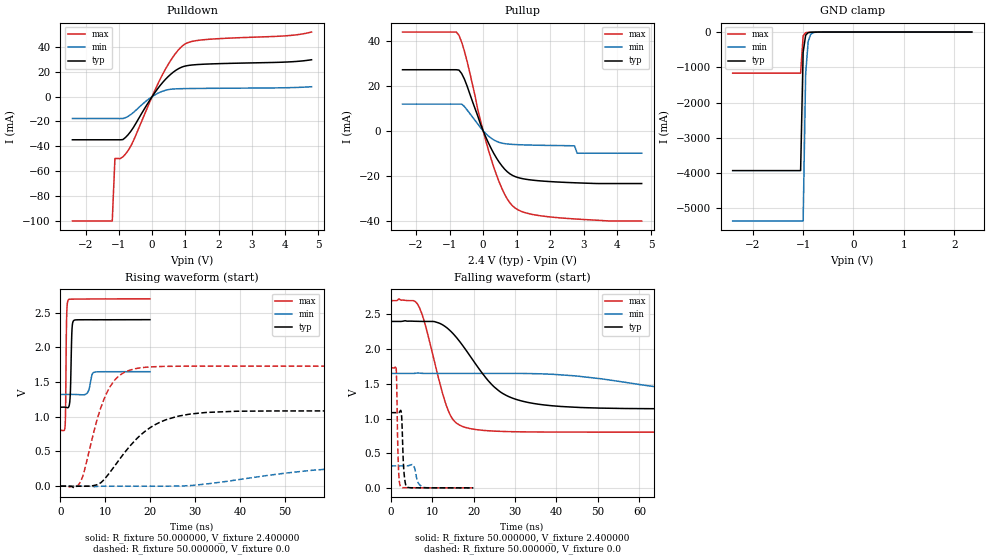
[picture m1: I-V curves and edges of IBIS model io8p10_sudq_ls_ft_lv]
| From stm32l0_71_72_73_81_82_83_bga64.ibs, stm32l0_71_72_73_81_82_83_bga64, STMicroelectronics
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|   Model io8p10_sudq_ls_ft_lv
[Model]  io8p10_sudq_ls_ft_lv
Model_type I/O
Polarity   Non-Inverting
Enable   Active-Low
Vinl =   0.720000V
Vinh =   1.680000V
Vmeas =  1.200000V
Cref =   50.000000pF
Rref =   100.000000M
Vref =   0.0V
C_comp   2.317700pF   2.286600pF   2.332700pF
[Temperature Range]   25.000000   0.105000k   -40.000000
[Pullup Reference]   2.400000V   1.650000V   2.700000V
[Pulldown Reference]   0.0V   0.0V   0.0V
[POWER Clamp Reference]   2.400000V   1.650000V   2.700000V
[GND Clamp Reference]   0.0V   0.0V   0.0V
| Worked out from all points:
|   slope of the pulldown table from 0 to 0.36 V, typ, clamps not added: 28.4 ohm
|   slope of the pullup table from 0 to 0.36 V, typ, clamps not added: 32.2 ohm
|   GND clamp passes 1 mA (typ) near -0.65 V on its own axis
|   rising waveform, R_fixture 50.000000, V_fixture 2.400000: 20-80 % time 276ps typ, 632ps min, 184ps max; typ from 1.14 V to 2.4 V
|   rising waveform, R_fixture 50.000000, V_fixture 0.0: 20-80 % time 9.37ns typ, 24.8ns min, 4.83ns max; typ from 0 V to 1.08 V
|   falling waveform, R_fixture 50.000000, V_fixture 2.400000: 20-80 % time 10.1ns typ, 27.4ns min, 4.97ns max; typ from 2.4 V to 1.14 V
|   falling waveform, R_fixture 50.000000, V_fixture 0.0: 20-80 % time 456ps typ, 833ps min, 355ps max; typ from 1.08 V to 0 V
[Pulldown]
|Voltage   I(typ)   I(min)   I(max)
-2.4V     -34.7mA    -17.61mA   -100mA
-1.2V     -34.7mA    -17.61mA   -100mA
-1.12V    -34.7mA    -17.61mA   -49.77mA
-960mV    -34.7mA    -17.61mA   -49.77mA
-720mV    -30.52mA   -15.81mA   -43.24mA
-560mV    -24.66mA   -12.69mA   -35.31mA
-80mV     -3.3mA     -1.497mA   -4.982mA
320mV     11.47mA    4.39mA     18.08mA
640mV     19.72mA    6.139mA    32.34mA
960mV     24.32mA    6.432mA    41.77mA
1.52V     26.01mA    6.613mA    45.64mA
4.8V      29.64mA    7.944mA    51.92mA
[Pullup]
|Voltage   I(typ)   I(min)   I(max)
-2.4V     27.21mA    11.89mA    44.01mA
-800mV    27.21mA    11.89mA    44.01mA
-720mV    27.06mA    11.89mA    42.53mA
-560mV    23.11mA    10.86mA    35.65mA
-80mV     3.011mA    1.496mA    4.671mA
320mV     -10.16mA   -4.078mA   -16.34mA
640mV     -17.08mA   -5.718mA   -28.28mA
960mV     -20.45mA   -6.129mA   -34.49mA
2V        -22.64mA   -6.529mA   -38.4mA
2.72V     -23.16mA   -6.7mA     -39.27mA
2.8V      -23.2mA    -10mA      -39.35mA
4.72V     -23.5mA    -10mA      -40.2mA
[GND_clamp]
|Voltage   I(typ)   I(min)   I(max)
-2.4V     -3.929A    -5.359A    -1.166A
-1.05V    -3.929A    -5.359A    -1.166A
-1V       -574.5mA   -5.359A    -109.1mA
-950mV    -90.02mA   -1.192A    -18.55mA
-900mV    -18.41mA   -269.7mA   -9.049mA
-850mV    -6.764mA   -63.59mA   -6.579mA
-800mV    -4.027mA   -16.66mA   -4.859mA
-650mV    -1.043mA   -1.218mA   -1.146mA
2.35V     0A         0A         0A
[POWER_clamp]
|Voltage   I(typ)   I(min)   I(max)
-2.4V     0A         0A         0A
0V        0A         0A         0A
[Ramp]
| variable   typ   min   max
dV/dt_r  0.65070/9.36030n   0.18997/24.76198n   1.03800/4.81922n
dV/dt_f  0.75696/10.10042n   0.19686/27.37086n   1.13786/4.96486n
R_load = 50.000000
[Rising Waveform]
R_fixture= 50.000000
V_fixture= 2.400000
V_fixture_min= 1.650000
V_fixture_max= 2.700000
|time   V(typ)   V(min)   V(max)
0s        1.138V     1.322V     803.6mV
1.041ns   1.138V     1.322V     870.2mV
1.161ns   1.137V     1.322V     1.19V
1.361ns   1.134V     1.322V     2.386V
1.722ns   1.133V     1.322V     2.683V
2.122ns   1.249V     1.322V     2.695V
2.563ns   2.246V     1.322V     2.696V
2.963ns   2.387V     1.322V     2.696V
7.608ns   2.399V     1.643V     2.699V
19.94ns   2.4V       1.65V      2.7V
[Rising Waveform]
R_fixture= 50.000000
V_fixture= 0.0
V_fixture_min= 0.0
V_fixture_max= 0.0
|time   V(typ)   V(min)   V(max)
0s        -472.8nV   -2.959uV   -194nV
4.505ns   -904.9uV   98.1uV     64.93mV
8.509ns   31.32mV    -905.1uV   1.033V
11.51ns   241mV      -198.6uV   1.478V
14.01ns   460mV      -201.1uV   1.632V
18.02ns   745.6mV    -191.8uV   1.708V
26.03ns   1.006V     1.047mV    1.729V
39.04ns   1.079V     87.63mV    1.73V
80.58ns   1.085V     302.6mV    1.73V
249.2ns   1.085V     316.6mV    1.73V
[Falling Waveform]
R_fixture= 50.000000
V_fixture= 2.400000
V_fixture_min= 1.650000
V_fixture_max= 2.700000
|time   V(typ)   V(min)   V(max)
0s        2.4V       1.65V      2.7V
6.507ns   2.401V     1.657V     2.65V
8.008ns   2.4V       1.651V     2.424V
14.01ns   2.286V     1.65V      1.098V
16.02ns   2.159V     1.65V      927.6mV
20.52ns   1.784V     1.65V      840.8mV
29.03ns   1.302V     1.65V      810.3mV
45.55ns   1.159V     1.608V     803.9mV
96.1ns    1.138V     1.344V     803.6mV
249.2ns   1.138V     1.322V     803.6mV
[Falling Waveform]
R_fixture= 50.000000
V_fixture= 0.0
V_fixture_min= 0.0
V_fixture_max= 0.0
|time   V(typ)   V(min)   V(max)
0s        1.085V     316.6mV    1.73V
1.321ns   1.085V     316.6mV    1.745V
1.441ns   1.085V     316.6mV    1.586V
1.882ns   1.084V     316.6mV    320mV
2.442ns   1.118V     316.6mV    17.18mV
2.683ns   1.014V     316.6mV    5.904mV
3.203ns   248.1mV    316.4mV    1.705mV
3.924ns   14.55mV    316.4mV    1.473mV
7.928ns   374uV      7.833mV    915.7uV
19.94ns   -472.8nV   -2.959uV   -194nV
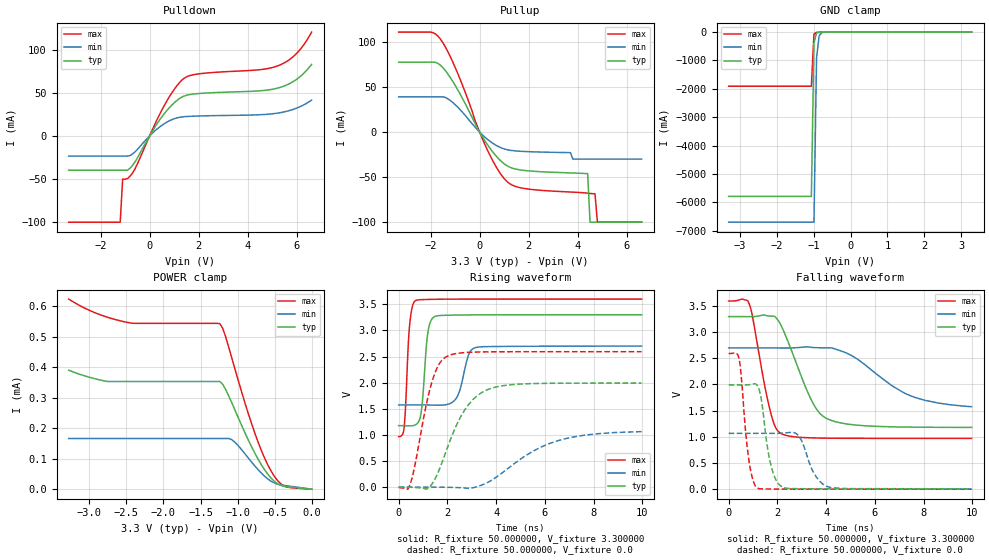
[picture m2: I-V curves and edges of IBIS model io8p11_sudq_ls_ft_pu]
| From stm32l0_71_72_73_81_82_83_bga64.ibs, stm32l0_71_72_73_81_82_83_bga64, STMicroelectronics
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|   Model io8p11_sudq_ls_ft_pu
[Model]  io8p11_sudq_ls_ft_pu
Model_type I/O
Polarity   Non-Inverting
Enable   Active-Low
Vinl =   0.990000V
Vinh =   2.310000V
Vmeas =  1.650000V
Cref =   50.000000pF
Rref =   100.000000M
Vref =   0.0V
C_comp   2.343000pF   2.309800pF   2.393900pF
[Temperature Range]   25.000000   0.125000k   -40.000000
[Pullup Reference]   3.300000V   2.700000V   3.600000V
[Pulldown Reference]   0.0V   0.0V   0.0V
[POWER Clamp Reference]   3.300000V   2.700000V   3.600000V
[GND Clamp Reference]   0.0V   0.0V   0.0V
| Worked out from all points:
|   slope of the pulldown table from 0 to 0.495 V, typ, clamps not added: 22.6 ohm
|   slope of the pullup table from 0 to 0.495 V, typ, clamps not added: 23.9 ohm
|   GND clamp passes 1 mA (typ) near -0.64 V on its own axis
|   rising waveform, R_fixture 50.000000, V_fixture 3.300000: 20-80 % time 209ps typ, 361ps min, 167ps max; typ from 1.18 V to 3.3 V
|   rising waveform, R_fixture 50.000000, V_fixture 0.0: 20-80 % time 1.17ns typ, 2.21ns min, 698ps max; typ from 0.001 V to 1.99 V
|   falling waveform, R_fixture 50.000000, V_fixture 3.300000: 20-80 % time 1.12ns typ, 2.07ns min, 641ps max; typ from 3.3 V to 1.18 V
|   falling waveform, R_fixture 50.000000, V_fixture 0.0: 20-80 % time 388ps typ, 564ps min, 310ps max; typ from 1.99 V to 0.001 V
[Pulldown]
|Voltage   I(typ)   I(min)   I(max)
-3.3V     -39.8mA    -23.38mA   -100mA
-1.2V     -39.8mA    -23.38mA   -100mA
-1.1V     -39.8mA    -23.38mA   -50.11mA
-900mV    -39.8mA    -23.38mA   -49.43mA
-700mV    -34.25mA   -21mA      -43.13mA
600mV     25.84mA    14.18mA    35.34mA
1V        38.32mA    19.82mA    53.81mA
1.4V      46.09mA    22.19mA    66.63mA
2V        49.05mA    23.02mA    71.83mA
5.2V      55.23mA    26.32mA    80.92mA
6V        65.77mA    32.26mA    95.84mA
6.6V      82.81mA    41.44mA    120.2mA
[Pullup]
|Voltage   I(typ)   I(min)   I(max)
-3.3V     77.64mA    39.15mA    111mA
-2V       77.64mA    39.15mA    111mA
-1.6V     74.25mA    39.15mA    103.3mA
-900mV    47.24mA    27.86mA    65.53mA
300mV     -13.29mA   -7.65mA    -18.99mA
1.2V      -38.62mA   -20mA      -56.79mA
3.7V      -45.29mA   -22.8mA    -66.51mA
4.4V      -46.01mA   -30mA      -67.77mA
4.5V      -100mA     -30mA      -68.06mA
4.7V      -100mA     -30mA      -68.41mA
4.8V      -100mA     -30mA      -100mA
6.6V      -100mA     -30mA      -100mA
[GND_clamp]
|Voltage   I(typ)   I(min)   I(max)
-3.3V     -5.787A    -6.696A    -1.906A
-1.06V    -5.787A    -6.696A    -1.906A
-990mV    -393.4mA   -6.696A    -70.75mA
-920mV    -33.02mA   -919.4mA   -10.9mA
-850mV    -6.829mA   -131.3mA   -6.521mA
-780mV    -3.478mA   -21.06mA   -4.208mA
3.28V     0A         0A         0A
[POWER_clamp]
|Voltage   I(typ)   I(min)   I(max)
-3.28V    390.5uA    166.4uA    624.1uA
-2.76V    353.6uA    166.4uA    564.6uA
-2.44V    353.6uA    166.4uA    545.3uA
-1.24V    353.6uA    166.4uA    543.5uA
-1.2V     344.2uA    166.4uA    528.2uA
-1.16V    327.1uA    166.4uA    499.5uA
-1.04V    262.6uA    155.2uA    398.8uA
-760mV    115.1uA    74.4uA     179.3uA
-560mV    39.86uA    27.94uA    65.07uA
-440mV    15uA       15.53uA    23.15uA
-360mV    8.745uA    12.05uA    9.089uA
0V        0A         0A         0A
[Ramp]
| variable   typ   min   max
dV/dt_r  1.19462/1.17303n   0.61247/2.09049n   1.55541/0.69549n
dV/dt_f  1.27146/1.11827n   0.59124/1.83665n   1.57744/0.63930n
R_load = 50.000000
[Rising Waveform]
R_fixture= 50.000000
V_fixture= 3.300000
V_fixture_min= 2.700000
V_fixture_max= 3.600000
|time   V(typ)   V(min)   V(max)
0s        1.178V     1.575V     967.9mV
220.2ps   1.177V     1.575V     1.13V
440.4ps   1.174V     1.575V     3.055V
700.7ps   1.198V     1.575V     3.572V
940.9ps   1.496V     1.575V     3.589V
1.221ns   3.023V     1.573V     3.593V
1.481ns   3.267V     1.571V     3.595V
2.362ns   3.294V     1.701V     3.599V
3.123ns   3.298V     2.666V     3.6V
9.97ns    3.3V       2.7V       3.6V
[Rising Waveform]
R_fixture= 50.000000
V_fixture= 0.0
V_fixture_min= 0.0
V_fixture_max= 0.0
|time   V(typ)   V(min)   V(max)
0s        1.228mV    1.825mV    -5.004mV
460.5ps   320.4uV    1.809mV    45.06mV
1.341ns   45.31mV    1.995mV    1.977V
1.642ns   310.2mV    1.629mV    2.342V
1.962ns   707.7mV    -435.1uV   2.499V
2.422ns   1.237V     -6.561mV   2.562V
2.843ns   1.567V     -20.6mV    2.58V
3.744ns   1.883V     114.2mV    2.59V
6.326ns   1.989V     859.2mV    2.593V
9.97ns    1.993V     1.064V     2.593V
[Falling Waveform]
R_fixture= 50.000000
V_fixture= 3.300000
V_fixture_min= 2.700000
V_fixture_max= 3.600000
|time   V(typ)   V(min)   V(max)
0s        3.3V       2.7V       3.6V
840.8ps   3.299V     2.7V       3.545V
1.682ns   3.311V     2.7V       1.54V
1.902ns   3.298V     2.7V       1.2V
2.142ns   3.139V     2.7V       1.064V
3.343ns   1.751V     2.715V     978.4mV
3.984ns   1.358V     2.702V     972.2mV
5.045ns   1.232V     2.554V     969.1mV
7.628ns   1.183V     1.754V     968mV
9.97ns    1.178V     1.575V     967.9mV
[Falling Waveform]
R_fixture= 50.000000
V_fixture= 0.0
V_fixture_min= 0.0
V_fixture_max= 0.0
|time   V(typ)   V(min)   V(max)
0s        1.993V     1.064V     2.593V
420.4ps   1.992V     1.064V     2.506V
820.8ps   1.995V     1.064V     580.8mV
1.181ns   1.974V     1.064V     16.75mV
1.742ns   442.5mV    1.064V     -2.385mV
2.222ns   33.24mV    1.068V     -3.285mV
2.883ns   4.461mV    1.01V      -4.104mV
3.504ns   3.224mV    297.6mV    -4.555mV
4.004ns   2.633mV    51.89mV    -4.752mV
9.97ns    1.228mV    1.825mV    -5.004mV
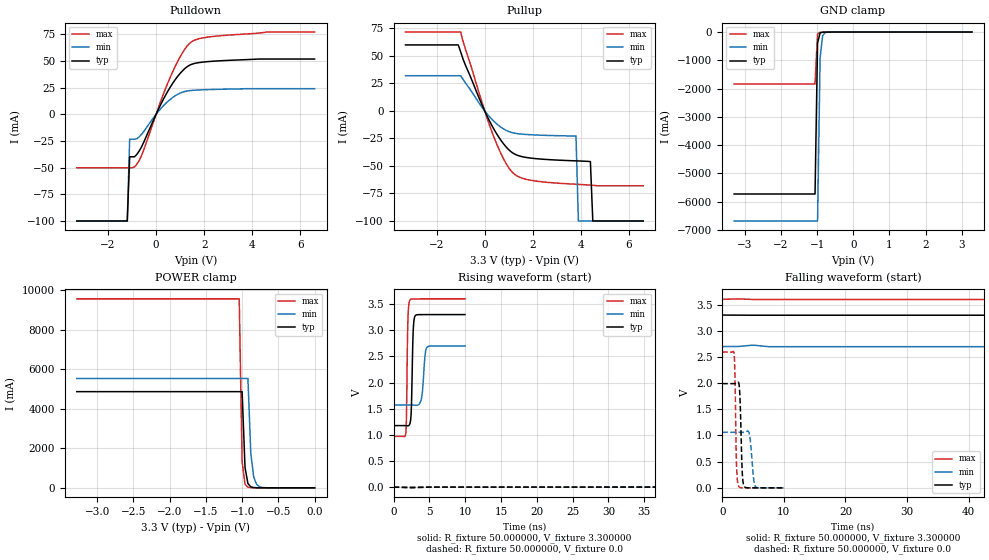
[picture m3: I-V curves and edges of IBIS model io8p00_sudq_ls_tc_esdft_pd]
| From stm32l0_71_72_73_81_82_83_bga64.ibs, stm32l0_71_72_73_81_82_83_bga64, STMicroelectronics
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|   Model io8p00_sudq_ls_tc_esdft_pd
[Model]  io8p00_sudq_ls_tc_esdft_pd
Model_type I/O
Polarity   Non-Inverting
Enable   Active-Low
Vinl =   0.990000V
Vinh =   2.310000V
Vmeas =  1.650000V
Cref =   50.000000pF
Rref =   100.000000M
Vref =   0.0V
C_comp   2.248300pF   2.207300pF   2.311900pF
[Temperature Range]   25.000000   0.125000k   -40.000000
[Pullup Reference]   3.300000V   2.700000V   3.600000V
[Pulldown Reference]   0.0V   0.0V   0.0V
[POWER Clamp Reference]   3.300000V   2.700000V   3.600000V
[GND Clamp Reference]   0.0V   0.0V   0.0V
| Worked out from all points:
|   slope of the pulldown table from 0 to 0.495 V, typ, clamps not added: 22.6 ohm
|   slope of the pullup table from 0 to 0.495 V, typ, clamps not added: 23.9 ohm
|   GND clamp passes 1 mA (typ) near -0.64 V on its own axis
|   POWER clamp passes 1 mA (typ) near -0.63 V on its own axis
|   rising waveform, R_fixture 50.000000, V_fixture 3.300000: 20-80 % time 209ps typ, 363ps min, 164ps max; typ from 1.18 V to 3.3 V
|   rising waveform, R_fixture 50.000000, V_fixture 0.0: 20-80 % time 210ns typ, 427ns min, 103ns max; typ from 0 V to 1.99 V
|   falling waveform, R_fixture 50.000000, V_fixture 3.300000: 20-80 % time 193ns typ, 384ns min, 106ns max; typ from 3.3 V to 1.18 V
|   falling waveform, R_fixture 50.000000, V_fixture 0.0: 20-80 % time 290ps typ, 458ps min, 227ps max; typ from 1.99 V to 0 V
[Pulldown]
|Voltage   I(typ)   I(min)   I(max)
-3.3V     -100mA     -100mA     -50.11mA
-1.2V     -100mA     -100mA     -50.11mA
-1.1V     -39.8mA    -23.38mA   -50.11mA
-900mV    -39.8mA    -23.38mA   -49.43mA
-600mV    -30.26mA   -18.59mA   -38.38mA
500mV     22.11mA    12.28mA    30.06mA
900mV     35.58mA    18.71mA    49.62mA
1.3V      44.74mA    21.88mA    64.23mA
1.7V      48.13mA    22.72mA    70.3mA
2.4V      49.79mA    23.3mA     73.03mA
4.6V      51.8mA     24mA       77.1mA
6.6V      51.8mA     24mA       77.1mA
[Pullup]
|Voltage   I(typ)   I(min)   I(max)
-3.3V     60mA       32mA       71.7mA
-1.1V     60mA       32mA       71.7mA
-1V       53.5mA     32mA       71.7mA
-100mV    4.893mA    2.926mA    6.861mA
400mV     -17.21mA   -9.812mA   -24.69mA
900mV     -32.92mA   -17.72mA   -48.15mA
1.3V      -39.75mA   -20.4mA    -58.47mA
3.8V      -45.36mA   -22.8mA    -66.6mA
3.9V      -45.44mA   -100mA     -66.72mA
4.4V      -46mA      -100mA     -67.4mA
4.5V      -100mA     -100mA     -67.56mA
6.6V      -100mA     -100mA     -68mA
[GND_clamp]
|Voltage   I(typ)   I(min)   I(max)
-3.3V     -5.732A    -6.689A    -1.842A
-1.06V    -5.732A    -6.689A    -1.842A
-990mV    -389.4mA   -6.689A    -68.35mA
-920mV    -32.58mA   -918.2mA   -10.73mA
-850mV    -6.776mA   -131mA     -6.518mA
-780mV    -3.484mA   -21.02mA   -4.216mA
3.28V     74.9uA     89.13uA    52.44uA
[POWER_clamp]
|Voltage   I(typ)   I(min)   I(max)
-3.28V    4.87A      5.538A     9.569A
-1.04V    4.87A      5.538A     9.569A
-1V       4.87A      5.538A     1.315A
-960mV    1.032A     5.538A     186.5mA
-920mV    222.2mA    5.538A     31.64mA
-880mV    50.73mA    1.734A     9.582mA
-840mV    13.93mA    544.8mA    5.668mA
-800mV    5.556mA    172.7mA    4.276mA
-760mV    3.231mA    55.84mA    3.297mA
-680mV    1.597mA    6.983mA    1.741mA
0V        0A         0A         0A
[Ramp]
| variable   typ   min   max
dV/dt_r  1.19412/0.20970u   0.60618/0.42769u   1.55520/0.10339u
dV/dt_f  1.27242/0.19304u   0.63624/0.38498u   1.57760/0.10596u
R_load = 50.000000
[Rising Waveform]
R_fixture= 50.000000
V_fixture= 3.300000
V_fixture_min= 2.700000
V_fixture_max= 3.600000
|time   V(typ)   V(min)   V(max)
0s        1.176V     1.571V     969.9mV
1.702ns   1.176V     1.571V     1.02V
2.002ns   1.172V     1.571V     3.192V
2.262ns   1.207V     1.571V     3.571V
2.482ns   1.517V     1.571V     3.595V
2.743ns   2.989V     1.569V     3.598V
2.963ns   3.261V     1.567V     3.599V
3.904ns   3.298V     1.705V     3.599V
4.645ns   3.299V     2.67V      3.599V
9.97ns    3.299V     2.698V     3.599V
[Rising Waveform]
R_fixture= 50.000000
V_fixture= 0.0
V_fixture_min= 0.0
V_fixture_max= 0.0
|time   V(typ)   V(min)   V(max)
0s        1.794nV    13.74nV    3.926nV
55.06ns   275.8uV    -16.63uV   81.26mV
112.6ns   80.83mV    125.2uV    963.1mV
177.7ns   429mV      2.008mV    1.946V
215.2ns   684.1mV    10.02mV    2.277V
272.8ns   1.075V     45.95mV    2.493V
412.9ns   1.683V     221.8mV    2.581V
545.5ns   1.894V     454.1mV    2.591V
858.4ns   1.983V     872.6mV    2.592V
1.246us   1.99V      1.06V      2.592V
[Falling Waveform]
R_fixture= 50.000000
V_fixture= 3.300000
V_fixture_min= 2.700000
V_fixture_max= 3.600000
|time   V(typ)   V(min)   V(max)
0s        3.299V     2.698V     3.599V
82.58ns   3.296V     2.695V     3.494V
145.1ns   3.209V     2.695V     2.587V
210.2ns   2.863V     2.692V     1.628V
247.7ns   2.608V     2.682V     1.251V
282.8ns   2.359V     2.664V     1.094V
397.9ns   1.617V     2.541V     997.6mV
510.5ns   1.321V     2.352V     978.9mV
863.4ns   1.191V     1.753V     970.4mV
1.246us   1.176V     1.571V     969.9mV
[Falling Waveform]
R_fixture= 50.000000
V_fixture= 0.0
V_fixture_min= 0.0
V_fixture_max= 0.0
|time   V(typ)   V(min)   V(max)
0s        1.99V      1.06V      2.592V
1.922ns   1.99V      1.06V      2.568V
2.322ns   1.991V     1.06V      448.6mV
2.643ns   2.015V     1.06V      36.53mV
2.883ns   1.723V     1.06V      6.041mV
3.263ns   276.2mV    1.06V      445.6uV
3.524ns   40.19mV    1.06V      159.9uV
4.404ns   152uV      1.027V     69.55uV
5.385ns   47.55uV    28.29mV    33.7uV
9.97ns    1.794nV    13.74nV    3.926nV
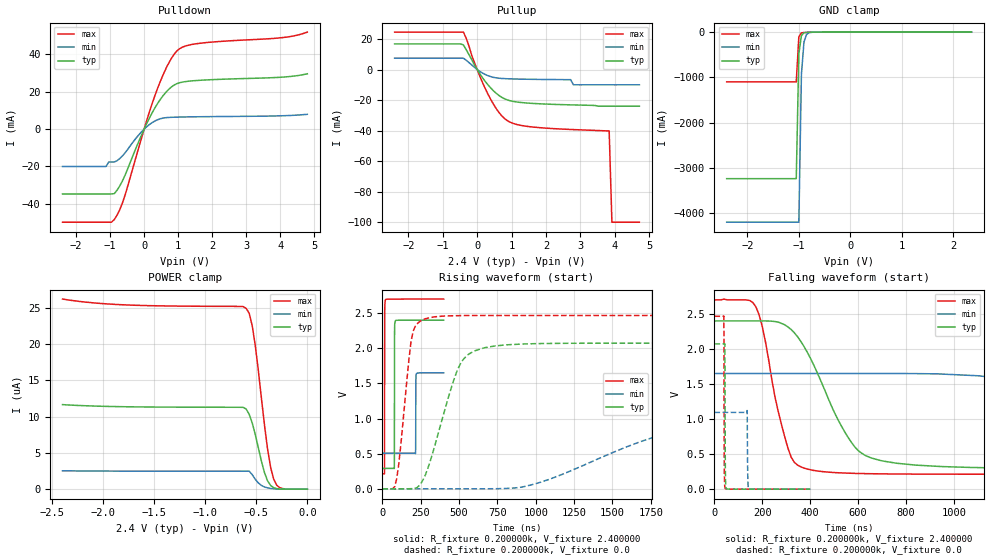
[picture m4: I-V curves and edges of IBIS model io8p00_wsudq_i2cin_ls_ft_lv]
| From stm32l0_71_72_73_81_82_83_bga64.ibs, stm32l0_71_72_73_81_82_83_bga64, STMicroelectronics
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|   Model io8p00_wsudq_i2cin_ls_ft_lv
[Model]  io8p00_wsudq_i2cin_ls_ft_lv
Model_type I/O
Polarity   Non-Inverting
Enable   Active-Low
Vinl =   0.720000V
Vinh =   1.680000V
Vmeas =  1.200000V
Cref =   50.000000pF
Rref =   100.000000M
Vref =   0.0V
C_comp   2.943600pF   2.919700pF   2.965100pF
[Temperature Range]   25.000000   0.105000k   -40.000000
[Pullup Reference]   2.400000V   1.650000V   2.700000V
[Pulldown Reference]   0.0V   0.0V   0.0V
[POWER Clamp Reference]   2.400000V   1.650000V   2.700000V
[GND Clamp Reference]   0.0V   0.0V   0.0V
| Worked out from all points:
|   slope of the pulldown table from 0 to 0.36 V, typ, clamps not added: 28.5 ohm
|   slope of the pullup table from 0 to 0.36 V, typ, clamps not added: 32.2 ohm
|   GND clamp passes 1 mA (typ) near -0.65 V on its own axis
|   rising waveform, R_fixture 0.200000k, V_fixture 2.400000: 20-80 % time 682ps typ, 843ps min, 768ps max; typ from 0.291 V to 2.4 V
|   rising waveform, R_fixture 0.200000k, V_fixture 0.0: 20-80 % time 169ns typ, 819ns min, 66.3ns max; typ from 0 V to 2.07 V
|   falling waveform, R_fixture 0.200000k, V_fixture 2.400000: 20-80 % time 180ns typ, 726ns min, 89.5ns max; typ from 2.4 V to 0.291 V
|   falling waveform, R_fixture 0.200000k, V_fixture 0.0: 20-80 % time 1.22ns typ, 1.77ns min, 1.04ns max; typ from 2.07 V to 0 V
[Pulldown]
|Voltage   I(typ)   I(min)   I(max)
-2.4V     -34.71mA   -20mA      -49.82mA
-1.12V    -34.71mA   -20mA      -49.82mA
-1.04V    -34.71mA   -17.6mA    -49.82mA
-880mV    -34.55mA   -17.6mA    -48.46mA
-560mV    -24.65mA   -12.68mA   -35.33mA
0V        326fA      0A         140fA
400mV     13.84mA    5.066mA    22.03mA
720mV     21.24mA    6.254mA    35.26mA
1.04V     24.82mA    6.464mA    43.03mA
1.6V      26.11mA    6.627mA    45.88mA
4V        27.76mA    7.125mA    48.87mA
4.8V      29.64mA    7.94mA     51.96mA
[Pullup]
|Voltage   I(typ)   I(min)   I(max)
-2.4V     16.77mA    7.419mA    24.51mA
-400mV    16.1mA     7.419mA    24.51mA
0V        80fA       6.14pA     10fA
320mV     -10.16mA   -4.078mA   -16.34mA
640mV     -17.08mA   -5.718mA   -28.28mA
960mV     -20.45mA   -6.128mA   -34.49mA
1.76V     -22.39mA   -6.47mA    -37.97mA
2.72V     -23.16mA   -6.64mA    -39.27mA
2.8V      -23.2mA    -10mA      -39.35mA
3.84V     -24mA      -10mA      -40.2mA
3.92V     -24mA      -10mA      -100mA
4.72V     -24mA      -10mA      -100mA
[GND_clamp]
|Voltage   I(typ)   I(min)   I(max)
-2.4V     -3.237A    -4.198A    -1.1A
-1.05V    -3.237A    -4.198A    -1.1A
-1V       -475.8mA   -4.198A    -104.2mA
-950mV    -76.24mA   -935.4mA   -18.39mA
-900mV    -16.61mA   -212.9mA   -9.105mA
-850mV    -6.547mA   -50.94mA   -6.589mA
-800mV    -3.998mA   -13.81mA   -4.86mA
-650mV    -1.043mA   -1.182mA   -1.146mA
2.35V     0A         0A         0A
[POWER_clamp]
|Voltage   I(typ)   I(min)   I(max)
-2.4V     11.64uA    2.525uA    26.17uA
-1.86V    11.37uA    2.488uA    25.42uA
-600mV    11.04uA    2.474uA    24.9uA
-570mV    10.3uA     2.473uA    24.21uA
-540mV    9.097uA    2uA        22.48uA
-510mV    7.497uA    1.35uA     19.73uA
-450mV    3.845uA    512.5nA    12.52uA
-390mV    1.154uA    175.5nA    5.528uA
-360mV    508.2nA    102.8nA    2.997uA
-330mV    204.4nA    60.39nA    1.375uA
-270mV    0A         0A         194.9nA
0V        0A         0A         0A
[Ramp]
| variable   typ   min   max
dV/dt_r  0.65070/0.30150u   0.18995/0.80885u   1.03800/0.14365u
dV/dt_f  0.75690/0.32139u   0.19674/0.84589u   1.13815/0.15977u
R_load = 50.000000
[Rising Waveform]
R_fixture= 0.200000k
V_fixture= 2.400000
V_fixture_min= 1.650000
V_fixture_max= 2.700000
|time   V(typ)   V(min)   V(max)
0s        290.7mV    507.1mV    212.9mV
14.01ns   290.7mV    507.1mV    219.7mV
15.22ns   290.7mV    507.1mV    2.411V
19.62ns   290.7mV    507.1mV    2.689V
77.68ns   289mV      507.1mV    2.7V
79.68ns   2.25V      507.1mV    2.7V
84.08ns   2.386V     507.1mV    2.7V
216.2ns   2.4V       502.4mV    2.7V
222.2ns   2.4V       1.639V     2.7V
400ns     2.4V       1.65V      2.7V
[Rising Waveform]
R_fixture= 0.200000k
V_fixture= 0.0
V_fixture_min= 0.0
V_fixture_max= 0.0
|time   V(typ)   V(min)   V(max)
0s        2.058nV    12.87nV    1.581nV
93.43ns   -110.6uV   12.86nV    141.6mV
200.2ns   2.446mV    12.87nV    2.238V
266.9ns   135.2mV    -23.39uV   2.407V
347ns     654.1mV    -23.4uV    2.449V
533.9ns   1.857V     91.37uV    2.465V
894.2ns   2.058V     19.85mV    2.467V
1.949us   2.072V     848.2mV    2.467V
2.683us   2.072V     1.051V     2.467V
13.33us   2.072V     1.095V     2.467V
[Falling Waveform]
R_fixture= 0.200000k
V_fixture= 2.400000
V_fixture_min= 1.650000
V_fixture_max= 2.700000
|time   V(typ)   V(min)   V(max)
0s        2.4V       1.65V      2.7V
173.5ns   2.4V       1.65V      2.598V
320.3ns   2.277V     1.65V      455.7mV
520.5ns   961mV      1.65V      233.1mV
627.3ns   485.6mV    1.65V      222mV
840.8ns   343.2mV    1.649V     215mV
1.348us   297mV      1.498V     212.9mV
2.162us   291mV      740.7mV    212.9mV
2.803us   290.7mV    566.6mV    212.9mV
13.33us   290.7mV    507.1mV    212.9mV
[Falling Waveform]
R_fixture= 0.200000k
V_fixture= 0.0
V_fixture_min= 0.0
V_fixture_max= 0.0
|time   V(typ)   V(min)   V(max)
0s        2.072V     1.095V     2.467V
39.24ns   2.072V     1.095V     2.471V
41.24ns   2.072V     1.095V     285.7mV
43.64ns   2.071V     1.095V     26.54mV
44.84ns   703.2mV    1.095V     13.18mV
48.85ns   15.21mV    1.095V     2.783mV
136.5ns   23.4uV     1.121V     136.9uV
139.3ns   23.51uV    155.8mV    137.3uV
143.3ns   23.68uV    6.813mV    137.8uV
400ns     2.058nV    12.87nV    1.581nV
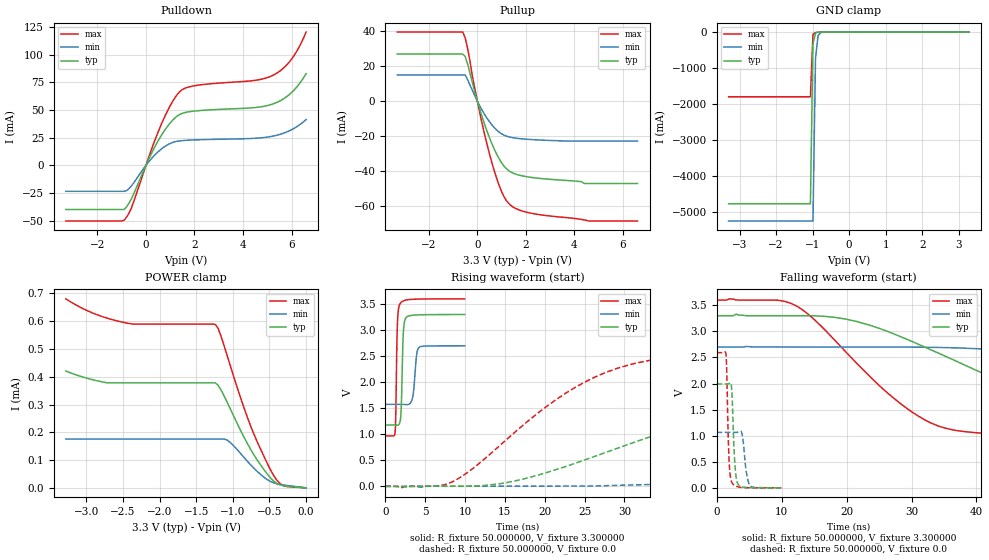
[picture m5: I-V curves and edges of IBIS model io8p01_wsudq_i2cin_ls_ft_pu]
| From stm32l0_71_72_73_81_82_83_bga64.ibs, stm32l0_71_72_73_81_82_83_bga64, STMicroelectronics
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|   Model io8p01_wsudq_i2cin_ls_ft_pu
[Model]  io8p01_wsudq_i2cin_ls_ft_pu
Model_type I/O
Polarity   Non-Inverting
Enable   Active-Low
Vinl =   0.990000V
Vinh =   2.310000V
Vmeas =  1.650000V
Cref =   50.000000pF
Rref =   100.000000M
Vref =   0.0V
C_comp   3.020400pF   2.988200pF   3.054500pF
[Temperature Range]   25.000000   0.125000k   -40.000000
[Pullup Reference]   3.300000V   2.700000V   3.600000V
[Pulldown Reference]   0.0V   0.0V   0.0V
[POWER Clamp Reference]   3.300000V   2.700000V   3.600000V
[GND Clamp Reference]   0.0V   0.0V   0.0V
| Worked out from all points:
|   slope of the pulldown table from 0 to 0.495 V, typ, clamps not added: 22.6 ohm
|   slope of the pullup table from 0 to 0.495 V, typ, clamps not added: 23.9 ohm
|   GND clamp passes 1 mA (typ) near -0.64 V on its own axis
|   rising waveform, R_fixture 50.000000, V_fixture 3.300000: 20-80 % time 222ps typ, 369ps min, 182ps max; typ from 1.18 V to 3.3 V
|   rising waveform, R_fixture 50.000000, V_fixture 0.0: 20-80 % time 27.1ns typ, 59.5ns min, 13.6ns max; typ from 0.001 V to 1.99 V
|   falling waveform, R_fixture 50.000000, V_fixture 3.300000: 20-80 % time 24.2ns typ, 53.1ns min, 13.3ns max; typ from 3.3 V to 1.18 V
|   falling waveform, R_fixture 50.000000, V_fixture 0.0: 20-80 % time 410ps typ, 573ps min, 333ps max; typ from 1.99 V to 0.001 V
[Pulldown]
|Voltage   I(typ)   I(min)   I(max)
-3.3V     -39.83mA   -23.37mA   -50.2mA
-900mV    -39.83mA   -23.37mA   -49.52mA
-600mV    -30.28mA   -18.59mA   -38.45mA
100mV     4.867mA    2.821mA    6.48mA
600mV     25.85mA    14.17mA    35.39mA
1V        38.33mA    19.81mA    53.88mA
1.4V      46.1mA     22.18mA    66.72mA
2V        49.07mA    23.02mA    71.93mA
4.4V      52.05mA    24.38mA    76.53mA
5.2V      55.25mA    26.31mA    81.02mA
6V        65.78mA    32.24mA    95.96mA
6.6V      82.83mA    41.41mA    120.4mA
[Pullup]
|Voltage   I(typ)   I(min)   I(max)
-3.3V     26.78mA    14.88mA    39.37mA
-600mV    26.78mA    14.88mA    39.37mA
-500mV    25.42mA    14.88mA    36.13mA
-400mV    21.16mA    12.2mA     30.01mA
-200mV    10.44mA    5.971mA    13.84mA
100mV     -4.685mA   -2.744mA   -6.647mA
600mV     -24.29mA   -13.56mA   -35.12mA
1V        -35.2mA    -18.69mA   -51.63mA
1.4V      -40.6mA    -20.72mA   -59.71mA
2.2V      -43.48mA   -21.92mA   -63.91mA
4.6V      -47mA      -22.8mA    -68.4mA
6.6V      -47mA      -22.8mA    -68.4mA
[GND_clamp]
|Voltage   I(typ)   I(min)   I(max)
-3.3V     -4.766A    -5.244A    -1.797A
-1.06V    -4.766A    -5.244A    -1.797A
-990mV    -326.6mA   -5.244A    -67.9mA
-920mV    -28.92mA   -722.1mA   -10.96mA
-850mV    -6.612mA   -104.2mA   -6.532mA
-780mV    -3.464mA   -17.27mA   -4.209mA
-500mV    -57.88uA   -167.8uA   -34.02uA
3.28V     0A         0A         0A
[POWER_clamp]
|Voltage   I(typ)   I(min)   I(max)
-3.28V    420.5uA    175.8uA    680.6uA
-2.72V    378.4uA    175.8uA    611.4uA
-2.4V     378.3uA    175.8uA    591.2uA
-1.24V    378.3uA    175.8uA    588.9uA
-1.2V     368.9uA    175.8uA    573.6uA
-1.08V    309.6uA    172.2uA    478.3uA
-920mV    220.5uA    131.5uA    344.5uA
-760mV    139.7uA    83.77uA    224.7uA
-480mV    33.95uA    22.2uA     61.82uA
-400mV    15.86uA    14.74uA    27.74uA
-320mV    8.147uA    10.83uA    9.34uA
0V        0A         0A         0A
[Ramp]
| variable   typ   min   max
dV/dt_r  1.19492/27.04723n   0.63581/59.53593n   1.55547/13.57437n
dV/dt_f  1.27344/24.19643n   0.66960/53.09159n   1.57816/13.29439n
R_load = 50.000000
[Rising Waveform]
R_fixture= 50.000000
V_fixture= 3.300000
V_fixture_min= 2.700000
V_fixture_max= 3.600000
|time   V(typ)   V(min)   V(max)
0s        1.178V     1.575V     969.7mV
1.241ns   1.177V     1.575V     1.039V
1.522ns   1.174V     1.575V     3.078V
1.862ns   1.244V     1.575V     3.508V
2.022ns   1.569V     1.575V     3.536V
2.282ns   2.969V     1.574V     3.56V
2.603ns   3.238V     1.57V      3.578V
3.423ns   3.285V     1.699V     3.591V
4.264ns   3.293V     2.671V     3.596V
9.97ns    3.3V       2.7V       3.6V
[Rising Waveform]
R_fixture= 50.000000
V_fixture= 0.0
V_fixture_min= 0.0
V_fixture_max= 0.0
|time   V(typ)   V(min)   V(max)
0s        1.061mV    1.817mV    656.1uV
8.008ns   3.229mV    4.287mV    61.17mV
15.02ns   66.99mV    4.294mV    872.2mV
25.03ns   508mV      7.544mV    2.001V
31.03ns   835.7mV    27.56mV    2.35V
39.04ns   1.222V     76.06mV    2.518V
57.56ns   1.751V     281.2mV    2.584V
82.08ns   1.948V     592.9mV    2.592V
138.6ns   1.992V     970.9mV    2.593V
249.2ns   1.993V     1.064V     2.593V
[Falling Waveform]
R_fixture= 50.000000
V_fixture= 3.300000
V_fixture_min= 2.700000
V_fixture_max= 3.600000
|time   V(typ)   V(min)   V(max)
0s        3.3V       2.7V       3.6V
12.01ns   3.3V       2.7V       3.504V
20.02ns   3.232V     2.7V       2.59V
29.53ns   2.836V     2.699V     1.503V
34.03ns   2.59V      2.693V     1.19V
39.54ns   2.277V     2.671V     1.061V
56.56ns   1.485V     2.525V     988.6mV
73.07ns   1.281V     2.303V     975.4mV
123.6ns   1.189V     1.744V     969.9mV
249.2ns   1.178V     1.575V     969.7mV
[Falling Waveform]
R_fixture= 50.000000
V_fixture= 0.0
V_fixture_min= 0.0
V_fixture_max= 0.0
|time   V(typ)   V(min)   V(max)
0s        1.993V     1.064V     2.593V
1.441ns   1.993V     1.064V     2.565V
1.542ns   1.992V     1.064V     2.321V
1.922ns   1.998V     1.064V     528.2mV
2.362ns   1.816V     1.064V     100.8mV
2.783ns   520mV      1.064V     46.83mV
3.263ns   79.71mV    1.068V     21.27mV
3.924ns   19mV       1.03V      7.529mV
5.085ns   4.878mV    53.9mV     3.451mV
9.97ns    1.061mV    1.817mV    656.1uV
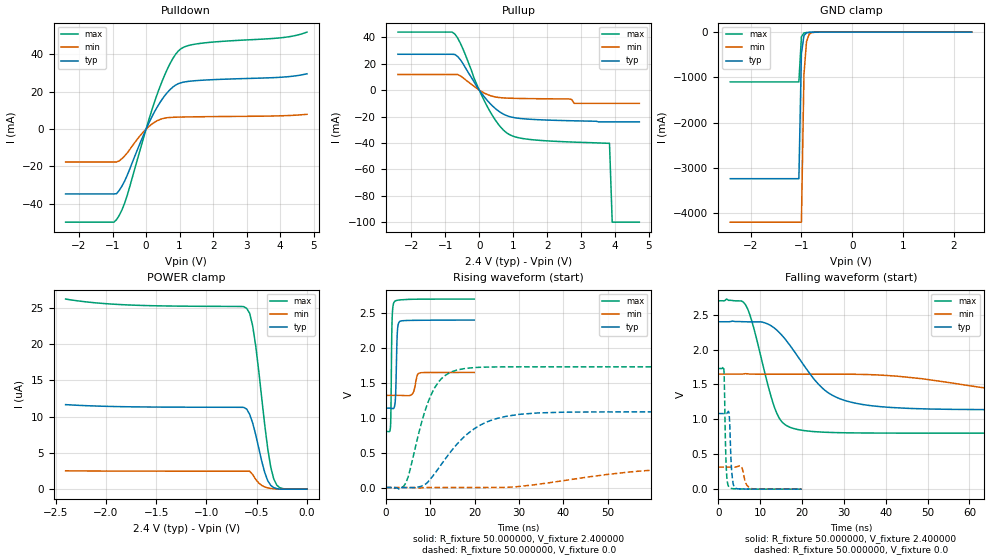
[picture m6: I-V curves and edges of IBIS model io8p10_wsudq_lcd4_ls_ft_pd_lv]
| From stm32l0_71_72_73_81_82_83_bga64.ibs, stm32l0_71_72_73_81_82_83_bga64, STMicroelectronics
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|   Model io8p10_wsudq_lcd4_ls_ft_pd_lv
[Model]  io8p10_wsudq_lcd4_ls_ft_pd_lv
Model_type I/O
Polarity   Non-Inverting
Enable   Active-Low
Vinl =   0.720000V
Vinh =   1.680000V
Vmeas =  1.200000V
Cref =   50.000000pF
Rref =   100.000000M
Vref =   0.0V
C_comp   3.178800pF   3.170000pF   3.206700pF
[Temperature Range]   25.000000   0.105000k   -40.000000
[Pullup Reference]   2.400000V   1.650000V   2.700000V
[Pulldown Reference]   0.0V   0.0V   0.0V
[POWER Clamp Reference]   2.400000V   1.650000V   2.700000V
[GND Clamp Reference]   0.0V   0.0V   0.0V
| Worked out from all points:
|   slope of the pulldown table from 0 to 0.36 V, typ, clamps not added: 28.5 ohm
|   slope of the pullup table from 0 to 0.36 V, typ, clamps not added: 32.2 ohm
|   GND clamp passes 1 mA (typ) near -0.64 V on its own axis
|   rising waveform, R_fixture 50.000000, V_fixture 2.400000: 20-80 % time 297ps typ, 642ps min, 211ps max; typ from 1.14 V to 2.4 V
|   rising waveform, R_fixture 50.000000, V_fixture 0.0: 20-80 % time 9.36ns typ, 24.7ns min, 4.83ns max; typ from 0 V to 1.08 V
|   falling waveform, R_fixture 50.000000, V_fixture 2.400000: 20-80 % time 10ns typ, 26.8ns min, 4.95ns max; typ from 2.4 V to 1.14 V
|   falling waveform, R_fixture 50.000000, V_fixture 0.0: 20-80 % time 489ps typ, 856ps min, 390ps max; typ from 1.08 V to 0 V
[Pulldown]
|Voltage   I(typ)   I(min)   I(max)
-2.4V     -34.71mA   -17.6mA    -49.82mA
-960mV    -34.71mA   -17.6mA    -49.82mA
-880mV    -34.55mA   -17.6mA    -48.46mA
-720mV    -30.52mA   -15.8mA    -43.27mA
-560mV    -24.65mA   -12.68mA   -35.33mA
0V        326fA      0A         140fA
400mV     13.84mA    5.066mA    22.03mA
720mV     21.25mA    6.254mA    35.26mA
1.04V     24.83mA    6.464mA    43.03mA
1.6V      26.11mA    6.627mA    45.88mA
4V        27.76mA    7.125mA    48.88mA
4.8V      29.63mA    7.94mA     51.96mA
[Pullup]
|Voltage   I(typ)   I(min)   I(max)
-2.4V     27.2mA     11.88mA    44.01mA
-720mV    27.06mA    11.88mA    42.53mA
-480mV    20.06mA    9.358mA    31.11mA
-160mV    6.59mA     3.051mA    9.467mA
240mV     -7.917mA   -3.299mA   -12.65mA
560mV     -15.67mA   -5.496mA   -25.76mA
880mV     -19.92mA   -6.062mA   -33.51mA
1.68V     -22.29mA   -6.449mA   -37.81mA
2.8V      -23.2mA    -10mA      -39.35mA
3.84V     -24mA      -10mA      -40.2mA
3.92V     -24mA      -10mA      -100mA
4.72V     -24mA      -10mA      -100mA
[GND_clamp]
|Voltage   I(typ)   I(min)   I(max)
-2.4V     -3.238A    -4.199A    -1.101A
-1.05V    -3.238A    -4.199A    -1.101A
-1V       -476.5mA   -4.199A    -104.7mA
-950mV    -76.69mA   -936.1mA   -18.75mA
-900mV    -16.87mA   -213.2mA   -9.366mA
-850mV    -6.718mA   -51.14mA   -6.786mA
-800mV    -4.121mA   -13.93mA   -5.004mA
-650mV    -1.082mA   -1.228mA   -1.183mA
2.35V     52.69uA    50.02uA    36.84uA
[POWER_clamp]
|Voltage   I(typ)   I(min)   I(max)
-2.4V     11.64uA    2.527uA    26.18uA
-1.86V    11.37uA    2.49uA     25.43uA
-600mV    11.04uA    2.475uA    24.9uA
-570mV    10.3uA     2.473uA    24.21uA
-540mV    9.097uA    2.001uA    22.48uA
-510mV    7.497uA    1.351uA    19.73uA
-450mV    3.846uA    513.2nA    12.52uA
-390mV    1.155uA    176.1nA    5.528uA
-360mV    508.6nA    103.4nA    2.997uA
-330mV    204.7nA    61.05nA    1.375uA
-270mV    0A         0A         195.3nA
0V        0A         0A         0A
[Ramp]
| variable   typ   min   max
dV/dt_r  0.65004/9.35231n   0.18967/24.62684n   1.03746/4.82050n
dV/dt_f  0.75702/10.03401n   0.19716/26.72500n   1.13800/4.93386n
R_load = 50.000000
[Rising Waveform]
R_fixture= 50.000000
V_fixture= 2.400000
V_fixture_min= 1.650000
V_fixture_max= 2.700000
|time   V(typ)   V(min)   V(max)
0s        1.137V     1.32V      802.9mV
1.041ns   1.137V     1.32V      868.3mV
1.161ns   1.136V     1.32V      1.178V
1.401ns   1.133V     1.32V      2.39V
1.882ns   1.147V     1.32V      2.657V
2.202ns   1.334V     1.32V      2.675V
2.603ns   2.239V     1.32V      2.682V
3.043ns   2.373V     1.32V      2.686V
7.688ns   2.395V     1.641V     2.698V
19.94ns   2.399V     1.649V     2.7V
[Rising Waveform]
R_fixture= 50.000000
V_fixture= 0.0
V_fixture_min= 0.0
V_fixture_max= 0.0
|time   V(typ)   V(min)   V(max)
0s        -626.9nV   -3.014uV   -476.7nV
4.505ns   -920.6uV   97.65uV    64.76mV
8.509ns   32.84mV    -974.9uV   1.031V
11.51ns   242.4mV    -198.5uV   1.477V
14.01ns   462.1mV    -200.1uV   1.631V
18.02ns   746.7mV    -178.2uV   1.707V
26.53ns   1.011V     1.728mV    1.728V
40.04ns   1.079V     98.18mV    1.729V
80.08ns   1.083V     301.8mV    1.729V
249.2ns   1.083V     316.1mV    1.729V
[Falling Waveform]
R_fixture= 50.000000
V_fixture= 2.400000
V_fixture_min= 1.650000
V_fixture_max= 2.700000
|time   V(typ)   V(min)   V(max)
0s        2.399V     1.649V     2.7V
6.507ns   2.399V     1.655V     2.644V
8.008ns   2.397V     1.649V     2.413V
14.01ns   2.279V     1.648V     1.085V
16.02ns   2.149V     1.648V     922.7mV
20.52ns   1.77V      1.648V     839.3mV
28.53ns   1.309V     1.648V     810mV
45.05ns   1.159V     1.605V     803.2mV
90.59ns   1.137V     1.348V     802.9mV
249.2ns   1.137V     1.32V      802.9mV
[Falling Waveform]
R_fixture= 50.000000
V_fixture= 0.0
V_fixture_min= 0.0
V_fixture_max= 0.0
|time   V(typ)   V(min)   V(max)
0s        1.083V     316.1mV    1.729V
1.321ns   1.083V     316.1mV    1.743V
1.441ns   1.083V     316.1mV    1.591V
1.722ns   1.083V     316.1mV    696.1mV
1.922ns   1.083V     316.1mV    321.3mV
2.563ns   1.095V     316.1mV    32.36mV
3.203ns   275.9mV    315.9mV    9.691mV
3.924ns   23.88mV    315.9mV    5.439mV
7.928ns   1.334mV    8.839mV    1.37mV
19.94ns   -626.9nV   -3.014uV   -476.7nV
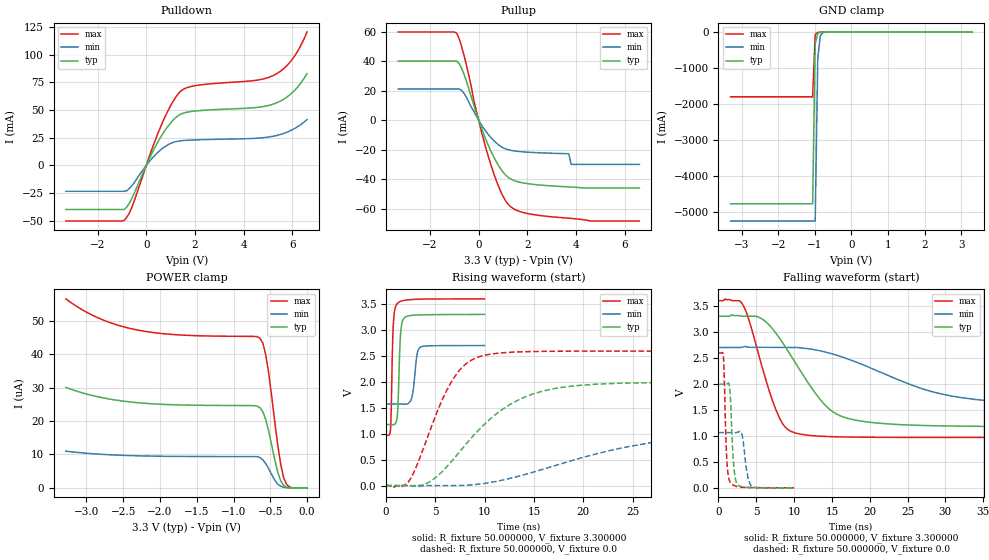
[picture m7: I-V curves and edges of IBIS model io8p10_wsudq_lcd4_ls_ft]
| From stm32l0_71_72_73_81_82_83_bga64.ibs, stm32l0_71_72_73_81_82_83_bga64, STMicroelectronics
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|   Model io8p10_wsudq_lcd4_ls_ft
[Model]  io8p10_wsudq_lcd4_ls_ft
Model_type I/O
Polarity   Non-Inverting
Enable   Active-Low
Vinl =   0.990000V
Vinh =   2.310000V
Vmeas =  1.650000V
Cref =   50.000000pF
Rref =   100.000000M
Vref =   0.0V
C_comp   3.263700pF   3.224800pF   3.309000pF
[Temperature Range]   25.000000   0.125000k   -40.000000
[Pullup Reference]   3.300000V   2.700000V   3.600000V
[Pulldown Reference]   0.0V   0.0V   0.0V
[POWER Clamp Reference]   3.300000V   2.700000V   3.600000V
[GND Clamp Reference]   0.0V   0.0V   0.0V
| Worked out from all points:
|   slope of the pulldown table from 0 to 0.495 V, typ, clamps not added: 22.6 ohm
|   slope of the pullup table from 0 to 0.495 V, typ, clamps not added: 23.9 ohm
|   GND clamp passes 1 mA (typ) near -0.64 V on its own axis
|   rising waveform, R_fixture 50.000000, V_fixture 3.300000: 20-80 % time 236ps typ, 376ps min, 201ps max; typ from 1.18 V to 3.3 V
|   rising waveform, R_fixture 50.000000, V_fixture 0.0: 20-80 % time 6.53ns typ, 13.6ns min, 3.48ns max; typ from 0 V to 1.99 V
|   falling waveform, R_fixture 50.000000, V_fixture 3.300000: 20-80 % time 5.96ns typ, 12.5ns min, 3.27ns max; typ from 3.3 V to 1.18 V
|   falling waveform, R_fixture 50.000000, V_fixture 0.0: 20-80 % time 414ps typ, 577ps min, 338ps max; typ from 1.99 V to 0 V
[Pulldown]
|Voltage   I(typ)   I(min)   I(max)
-3.3V     -39.83mA   -23.37mA   -50.2mA
-900mV    -39.83mA   -23.37mA   -49.52mA
-600mV    -30.28mA   -18.59mA   -38.45mA
500mV     22.11mA    12.28mA    30.1mA
1V        38.33mA    19.81mA    53.88mA
1.4V      46.1mA     22.18mA    66.72mA
2V        49.07mA    23.01mA    71.93mA
4.4V      52.05mA    24.38mA    76.53mA
5.2V      55.25mA    26.31mA    81.02mA
5.6V      59.18mA    28.57mA    86.57mA
6V        65.79mA    32.24mA    95.97mA
6.6V      82.83mA    41.41mA    120.4mA
[Pullup]
|Voltage   I(typ)   I(min)   I(max)
-3.3V     40.03mA    21.09mA    59.71mA
-900mV    40.03mA    21.09mA    58.93mA
-800mV    38.38mA    21.09mA    55.25mA
-600mV    31.19mA    18.17mA    44.03mA
0V        90fA       25.2pA     -900fA
500mV     -20.88mA   -11.78mA   -30.07mA
900mV     -32.92mA   -17.72mA   -48.15mA
1.3V      -39.75mA   -20.41mA   -58.47mA
2V        -43.05mA   -21.73mA   -63.29mA
3.7V      -45.29mA   -22.8mA    -66.5mA
3.8V      -45.39mA   -30mA      -66.64mA
6.6V      -46mA      -30mA      -68.41mA
[GND_clamp]
|Voltage   I(typ)   I(min)   I(max)
-3.3V     -4.767A    -5.245A    -1.798A
-1.06V    -4.767A    -5.245A    -1.798A
-990mV    -327.3mA   -5.245A    -68.38mA
-920mV    -29.22mA   -722.7mA   -11.24mA
-850mV    -6.771mA   -104.4mA   -6.721mA
-780mV    -3.56mA    -17.38mA   -4.326mA
-500mV    -59.41uA   -172uA     -34.91uA
3.28V     0A         0A         0A
[POWER_clamp]
|Voltage   I(typ)   I(min)   I(max)
-3.28V    30.09uA    10.99uA    56.63uA
-2.84V    27.27uA    10.11uA    50.92uA
-2.32V    25.55uA    9.609uA    47.36uA
-640mV    24.06uA    9.1uA      44.84uA
-600mV    22.76uA    8.366uA    43.37uA
-560mV    20.32uA    7.212uA    39.74uA
-520mV    16.86uA    5.676uA    34.15uA
-400mV    4.842uA    1.146uA    13.11uA
-360mV    2.185uA    478.4nA    7.29uA
-320mV    773nA      181.6nA    3.214uA
-240mV    60.58nA    0A         296.5nA
0V        0A         0A         0A
[Ramp]
| variable   typ   min   max
dV/dt_r  1.19496/6.52402n   0.62928/13.55694n   1.55568/3.47436n
dV/dt_f  1.27374/5.94974n   0.65334/12.42490n   1.57856/3.26796n
R_load = 50.000000
[Rising Waveform]
R_fixture= 50.000000
V_fixture= 3.300000
V_fixture_min= 2.700000
V_fixture_max= 3.600000
|time   V(typ)   V(min)   V(max)
0s        1.177V     1.573V     969mV
440.4ps   1.176V     1.573V     1.076V
720.7ps   1.173V     1.573V     3.081V
1.081ns   1.275V     1.574V     3.498V
1.201ns   1.567V     1.574V     3.523V
1.461ns   2.921V     1.572V     3.552V
1.822ns   3.231V     1.568V     3.572V
2.583ns   3.282V     1.684V     3.587V
3.423ns   3.291V     2.662V     3.595V
9.97ns    3.3V       2.7V       3.6V
[Rising Waveform]
R_fixture= 50.000000
V_fixture= 0.0
V_fixture_min= 0.0
V_fixture_max= 0.0
|time   V(typ)   V(min)   V(max)
0s        718.3nV    -6.591uV   358.2uV
2.302ns   -2.305mV   -1.631mV   81.18mV
4.204ns   48.28mV    -976.5uV   935.4mV
6.507ns   438.1mV    -605.4uV   1.963V
8.008ns   777.8mV    5.104mV    2.332V
9.51ns    1.094V     30.18mV    2.488V
13.61ns   1.669V     188.3mV    2.578V
18.12ns   1.901V     441.3mV    2.591V
30.43ns   1.989V     914.7mV    2.593V
49.85ns   1.992V     1.062V     2.593V
[Falling Waveform]
R_fixture= 50.000000
V_fixture= 3.300000
V_fixture_min= 2.700000
V_fixture_max= 3.600000
|time   V(typ)   V(min)   V(max)
0s        3.3V       2.7V       3.6V
3.303ns   3.301V     2.711V     3.501V
5.405ns   3.274V     2.703V     2.515V
7.508ns   2.992V     2.702V     1.535V
8.609ns   2.762V     2.701V     1.206V
9.91ns    2.465V     2.7V       1.067V
14.31ns   1.561V     2.605V     988mV
17.92ns   1.308V     2.435V     975.9mV
30.13ns   1.191V     1.785V     969.4mV
49.85ns   1.177V     1.573V     969mV
[Falling Waveform]
R_fixture= 50.000000
V_fixture= 0.0
V_fixture_min= 0.0
V_fixture_max= 0.0
|time   V(typ)   V(min)   V(max)
0s        1.992V     1.062V     2.593V
640.6ps   1.992V     1.062V     2.54V
1.101ns   1.997V     1.062V     543.1mV
1.542ns   1.815V     1.062V     109.9mV
2.002ns   455.3mV    1.061V     49.48mV
2.482ns   74.43mV    1.067V     24.06mV
3.143ns   20.04mV    1.002V     10.49mV
3.744ns   9.282mV    315.2mV    7.237mV
4.384ns   5.326mV    34.16mV    3.979mV
9.97ns    718.3nV    -6.591uV   358.2uV
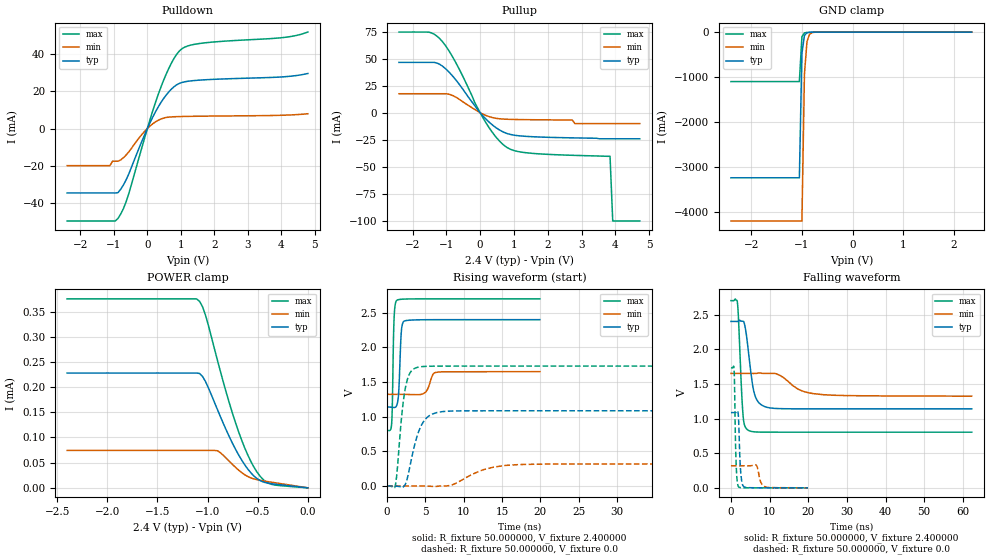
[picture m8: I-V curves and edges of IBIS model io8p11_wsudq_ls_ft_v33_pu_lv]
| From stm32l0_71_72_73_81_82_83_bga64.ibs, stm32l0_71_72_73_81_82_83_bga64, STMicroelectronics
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|   Model io8p11_wsudq_ls_ft_v33_pu_lv
[Model]  io8p11_wsudq_ls_ft_v33_pu_lv
Model_type I/O
Polarity   Non-Inverting
Enable   Active-Low
Vinl =   0.720000V
Vinh =   1.680000V
Vmeas =  1.200000V
Cref =   50.000000pF
Rref =   100.000000M
Vref =   0.0V
C_comp   2.582000pF   2.574200pF   2.601000pF
[Temperature Range]   25.000000   0.105000k   -40.000000
[Pullup Reference]   2.400000V   1.650000V   2.700000V
[Pulldown Reference]   0.0V   0.0V   0.0V
[POWER Clamp Reference]   2.400000V   1.650000V   2.700000V
[GND Clamp Reference]   0.0V   0.0V   0.0V
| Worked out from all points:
|   slope of the pulldown table from 0 to 0.36 V, typ, clamps not added: 28.5 ohm
|   slope of the pullup table from 0 to 0.36 V, typ, clamps not added: 32.2 ohm
|   GND clamp passes 1 mA (typ) near -0.65 V on its own axis
|   rising waveform, R_fixture 50.000000, V_fixture 2.400000: 20-80 % time 279ps typ, 633ps min, 195ps max; typ from 1.14 V to 2.4 V
|   rising waveform, R_fixture 50.000000, V_fixture 0.0: 20-80 % time 1.58ns typ, 3.84ns min, 926ps max; typ from 0.001 V to 1.09 V
|   falling waveform, R_fixture 50.000000, V_fixture 2.400000: 20-80 % time 1.79ns typ, 5.22ns min, 915ps max; typ from 2.4 V to 1.14 V
|   falling waveform, R_fixture 50.000000, V_fixture 0.0: 20-80 % time 485ps typ, 869ps min, 385ps max; typ from 1.09 V to 0.001 V
[Pulldown]
|Voltage   I(typ)   I(min)   I(max)
-2.4V     -34.71mA   -20mA      -49.82mA
-1.12V    -34.71mA   -20mA      -49.82mA
-1.04V    -34.71mA   -17.61mA   -49.82mA
-880mV    -34.55mA   -17.61mA   -48.46mA
-560mV    -24.65mA   -12.68mA   -35.33mA
0V        0A         0A         0A
400mV     13.84mA    5.066mA    22.03mA
720mV     21.25mA    6.254mA    35.26mA
1.04V     24.83mA    6.464mA    43.02mA
1.6V      26.11mA    6.627mA    45.88mA
4V        27.76mA    7.125mA    48.88mA
4.8V      29.64mA    7.94mA     51.96mA
[Pullup]
|Voltage   I(typ)   I(min)   I(max)
-2.4V     46.57mA    17.6mA     74.62mA
-1.52V    46.57mA    17.6mA     74.51mA
-1.2V     44.84mA    17.6mA     68.63mA
-720mV    30.37mA    14.45mA    46.27mA
-160mV    6.617mA    3.074mA    9.467mA
160mV     -5.477mA   -2.361mA   -8.695mA
480mV     -14.04mA   -5.167mA   -22.91mA
800mV     -19.21mA   -5.978mA   -32.18mA
1.52V     -22.07mA   -6.4mA     -37.42mA
3.84V     -24mA      -10mA      -40.2mA
3.92V     -24mA      -10mA      -100mA
4.72V     -24mA      -10mA      -100mA
[GND_clamp]
|Voltage   I(typ)   I(min)   I(max)
-2.4V     -3.237A    -4.198A    -1.1A
-1.05V    -3.237A    -4.198A    -1.1A
-1V       -475.9mA   -4.198A    -104.3mA
-950mV    -76.36mA   -935.5mA   -18.56mA
-900mV    -16.77mA   -213mA     -9.293mA
-850mV    -6.713mA   -51.08mA   -6.724mA
-800mV    -4.108mA   -13.94mA   -4.924mA
-650mV    -1.048mA   -1.2mA     -1.149mA
2.35V     0A         0A         0A
[POWER_clamp]
|Voltage   I(typ)   I(min)   I(max)
-2.4V     228uA      74.29uA    375.2uA
-1.11V    228uA      74.29uA    375.2uA
-1.08V    227.1uA    74.29uA    370.5uA
-1.02V    210.9uA    74.29uA    342.6uA
-900mV    154.7uA    73.58uA    252.2uA
-810mV    113.1uA    58.15uA    186.8uA
-720mV    76.17uA    40.44uA    128.5uA
-630mV    45.92uA    26.04uA    79.56uA
-540mV    23.97uA    17.88uA    41.93uA
-450mV    12.07uA    14.02uA    17.32uA
-390mV    9.04uA     12.05uA    8.867uA
0V        0A         0A         0A
[Ramp]
| variable   typ   min   max
dV/dt_r  0.65095/1.58012n   0.19037/3.83599n   1.03799/0.92277n
dV/dt_f  0.75618/1.78528n   0.19404/5.21585n   1.13779/0.91185n
R_load = 50.000000
[Rising Waveform]
R_fixture= 50.000000
V_fixture= 2.400000
V_fixture_min= 1.650000
V_fixture_max= 2.700000
|time   V(typ)   V(min)   V(max)
0s        1.14V      1.323V     803.1mV
600.6ps   1.137V     1.323V     889.7mV
920.9ps   1.133V     1.323V     2.407V
1.281ns   1.167V     1.323V     2.679V
1.522ns   1.349V     1.323V     2.689V
1.882ns   2.243V     1.323V     2.694V
2.242ns   2.38V      1.322V     2.697V
4.925ns   2.399V     1.346V     2.7V
6.446ns   2.4V       1.64V      2.7V
19.94ns   2.4V       1.65V      2.7V
[Rising Waveform]
R_fixture= 50.000000
V_fixture= 0.0
V_fixture_min= 0.0
V_fixture_max= 0.0
|time   V(typ)   V(min)   V(max)
0s        854.4uV    1.333mV    747.5uV
1.001ns   556.4uV    1.325mV    -23.64mV
1.251ns   -1.738mV   1.32mV     132.4mV
2.377ns   21.38mV    1.411mV    1.404V
3.003ns   290.8mV    1.411mV    1.632V
4.004ns   745.5mV    1.179mV    1.713V
5.506ns   1.014V     -2.257mV   1.728V
8.383ns   1.082V     13.51mV    1.73V
17.27ns   1.086V     309.8mV    1.73V
62.31ns   1.086V     318.6mV    1.73V
[Falling Waveform]
R_fixture= 50.000000
V_fixture= 2.400000
V_fixture_min= 1.650000
V_fixture_max= 2.700000
|time   V(typ)   V(min)   V(max)
0s        2.4V       1.65V      2.7V
1.627ns   2.399V     1.65V      2.696V
1.877ns   2.403V     1.65V      2.523V
2.753ns   2.403V     1.65V      1.393V
3.128ns   2.403V     1.65V      1.049V
4.505ns   1.974V     1.65V      830mV
6.131ns   1.348V     1.65V      808mV
9.259ns   1.163V     1.651V     803.5mV
21.27ns   1.14V      1.36V      803.1mV
62.31ns   1.14V      1.323V     803.1mV
[Falling Waveform]
R_fixture= 50.000000
V_fixture= 0.0
V_fixture_min= 0.0
V_fixture_max= 0.0
|time   V(typ)   V(min)   V(max)
0s        1.086V     318.6mV    1.73V
800.8ps   1.086V     318.6mV    1.721V
1.321ns   1.088V     318.6mV    386.1mV
1.562ns   1.103V     318.6mV    128.9mV
1.962ns   1.001V     318.6mV    15.76mV
2.482ns   260.4mV    318.6mV    4.532mV
3.243ns   22.71mV    318.6mV    2.638mV
6.567ns   1.673mV    327.5mV    824.5uV
9.209ns   1.014mV    9.443mV    752.1uV
19.94ns   854.4uV    1.333mV    747.5uV
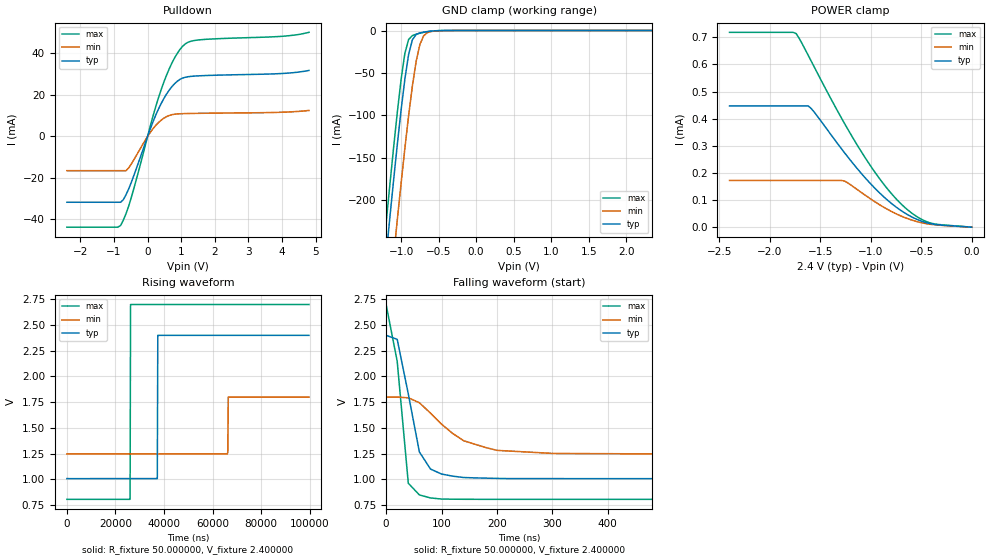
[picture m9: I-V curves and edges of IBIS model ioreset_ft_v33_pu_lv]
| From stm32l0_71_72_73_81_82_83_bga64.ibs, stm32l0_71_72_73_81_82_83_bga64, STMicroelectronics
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|   Model ioreset_ft_v33_pu_lv
[Model]  ioreset_ft_v33_pu_lv
Model_type I/O_open_drain
Polarity   Inverting
Enable   Active-High
Vinl =   0.720000V
Vinh =   1.680000V
Vmeas =  1.200000V
Cref =   1.0000000000000001E-7F
Rref =   1.000000k
Vref =   2.400000V
C_comp   2.007500pF   1.959500pF   2.081200pF
[Temperature Range]   25.000000   0.125000k   -40.000000
[Pullup Reference]   2.400000V   1.800000V   2.700000V
[Pulldown Reference]   0.0V   0.0V   0.0V
[POWER Clamp Reference]   2.400000V   1.800000V   2.700000V
[GND Clamp Reference]   0.0V   0.0V   0.0V
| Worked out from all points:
|   slope of the pulldown table from 0 to 0.36 V, typ, clamps not added: 25 ohm
|   GND clamp passes 1 mA (typ) near -0.62 V on its own axis
|   rising waveform, R_fixture 50.000000, V_fixture 2.400000: 20-80 % time 120ns typ, 125ns min, 120ns max; typ from 1.01 V to 2.4 V
|   falling waveform, R_fixture 50.000000, V_fixture 2.400000: 20-80 % time 30.3ns typ, 79.4ns min, 22.6ns max; typ from 2.4 V to 1.01 V
[Pulldown]
|Voltage   I(typ)   I(min)   I(max)
-2.4V     -31.73mA   -16.51mA   -43.74mA
-800mV    -31.73mA   -16.51mA   -42.87mA
-640mV    -28.07mA   -16.51mA   -37.19mA
-480mV    -21.98mA   -13.17mA   -29.21mA
80mV      3.63mA     1.966mA    5.014mA
320mV     13.07mA    6.631mA    18.44mA
480mV     18.16mA    8.738mA    26.02mA
800mV     25.38mA    10.72mA    37.77mA
1.12V     28.53mA    11.02mA    44.6mA
1.6V      29.27mA    11.16mA    46.65mA
4V        30.35mA    11.67mA    48.29mA
4.8V      31.81mA    12.51mA    50.19mA
[GND_clamp]
|Voltage   I(typ)   I(min)   I(max)
-2.4V     -1.423A    -1.507A    -1.391A
-1.25V    -311.2mA   -401.9mA   -273.3mA
-1.2V     -265.4mA   -356.1mA   -227.2mA
-1.15V    -220.4mA   -310.8mA   -181.9mA
-1.1V     -176.3mA   -266.2mA   -137.9mA
-1.05V    -133.8mA   -222.5mA   -95.87mA
-950mV    -57.3mA    -138.9mA   -26.98mA
-900mV    -28.27mA   -100.4mA   -10.59mA
-850mV    -11.01mA   -65.54mA   -5.958mA
-750mV    -2.834mA   -16.5mA    -3.178mA
-600mV    -750uA     -1.164mA   -738.3uA
2.35V     0A         0A         0A
[POWER_clamp]
|Voltage   I(typ)   I(min)   I(max)
-2.4V     446.9uA    172.2uA    718.4uA
-1.74V    446.9uA    172.2uA    713.9uA
-1.62V    446.9uA    172.2uA    633.6uA
-1.59V    437.4uA    172.2uA    612uA
-1.26V    274.3uA    170.2uA    382.2uA
-990mV    155.4uA    101.2uA    219.3uA
-870mV    111.5uA    73.17uA    157.7uA
-750mV    74.36uA    49.52uA    104.9uA
-600mV    38.95uA    26.97uA    53.56uA
-450mV    16.48uA    12.83uA    20.79uA
-330mV    8.637uA    7.585uA    9.914uA
0V        0A         0A         0A
[Ramp]
| variable   typ   min   max
dV/dt_r  0.83580/59.96986n   0.33168/60.28353n   1.13660/59.99715n
dV/dt_f  0.83574/61.97553n   0.33168/0.12818u   1.13660/60.09104n
R_load = 50.000000
[Rising Waveform]
R_fixture= 50.000000
V_fixture= 2.400000
V_fixture_min= 1.800000
V_fixture_max= 2.700000
|time   V(typ)   V(min)   V(max)
0s        1.007V     1.247V     805.7mV
26.03us   1.007V     1.247V     805.6mV
26.23us   1.007V     1.247V     2.7V
37.24us   1.007V     1.247V     2.7V
37.44us   2.4V       1.247V     2.7V
66.07us   2.4V       1.247V     2.7V
66.27us   2.4V       1.267V     2.7V
66.47us   2.4V       1.8V       2.7V
99.7us    2.4V       1.8V       2.7V
[Falling Waveform]
R_fixture= 50.000000
V_fixture= 2.400000
V_fixture_min= 1.800000
V_fixture_max= 2.700000
|time   V(typ)   V(min)   V(max)
0s        2.4V       1.8V       2.7V
20.02ns   2.361V     1.8V       2.147V
40.04ns   1.83V      1.793V     962.2mV
60.06ns   1.266V     1.745V     848.5mV
80.08ns   1.1V       1.644V     819.2mV
100.1ns   1.051V     1.536V     808.5mV
140.1ns   1.018V     1.375V     806.1mV
200.2ns   1.009V     1.282V     805.7mV
320.3ns   1.007V     1.251V     805.7mV
9.97us    1.007V     1.247V     805.7mV
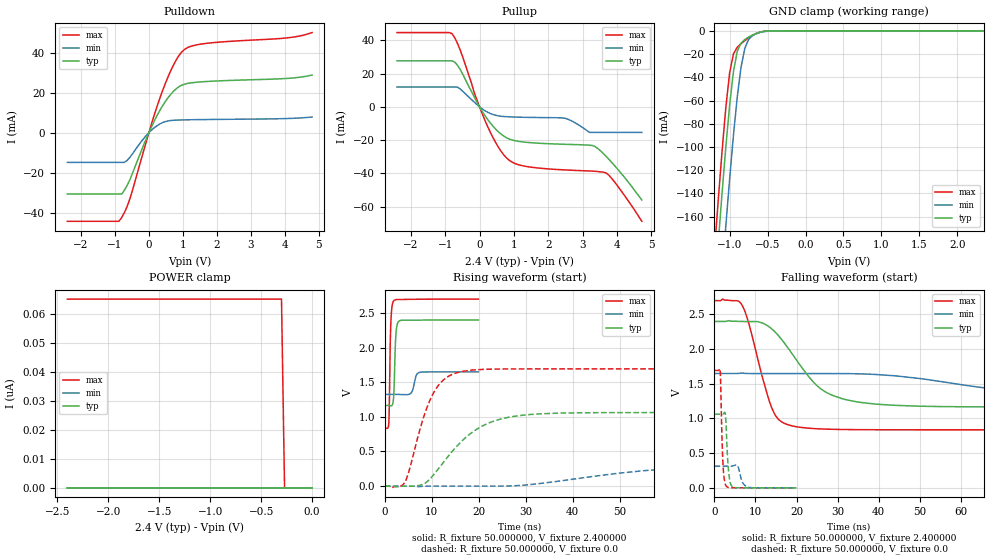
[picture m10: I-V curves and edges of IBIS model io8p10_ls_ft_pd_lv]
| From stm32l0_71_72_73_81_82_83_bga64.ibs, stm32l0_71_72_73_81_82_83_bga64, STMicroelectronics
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|   Model io8p10_ls_ft_pd_lv
[Model]  io8p10_ls_ft_pd_lv
Model_type I/O
Polarity   Non-Inverting
Enable   Active-Low
Vinl =   0.720000V
Vinh =   1.680000V
Vmeas =  1.200000V
Cref =   50.000000pF
Rref =   100.000000M
Vref =   0.0V
C_comp   4.521100pF   4.438000pF   4.578000pF
[Temperature Range]   25.000000   0.105000k   -40.000000
[Pullup Reference]   2.400000V   1.650000V   2.700000V
[Pulldown Reference]   0.0V   0.0V   0.0V
[POWER Clamp Reference]   2.400000V   1.650000V   2.700000V
[GND Clamp Reference]   0.0V   0.0V   0.0V
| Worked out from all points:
|   slope of the pulldown table from 0 to 0.36 V, typ, clamps not added: 29.5 ohm
|   slope of the pullup table from 0 to 0.36 V, typ, clamps not added: 33.2 ohm
|   GND clamp passes 1 mA (typ) near -0.59 V on its own axis
|   rising waveform, R_fixture 50.000000, V_fixture 2.400000: 20-80 % time 360ps typ, 684ps min, 300ps max; typ from 1.17 V to 2.4 V
|   rising waveform, R_fixture 50.000000, V_fixture 0.0: 20-80 % time 9.31ns typ, 24.7ns min, 4.8ns max; typ from 0 V to 1.06 V
|   falling waveform, R_fixture 50.000000, V_fixture 2.400000: 20-80 % time 10.1ns typ, 27.2ns min, 5.05ns max; typ from 2.4 V to 1.17 V
|   falling waveform, R_fixture 50.000000, V_fixture 0.0: 20-80 % time 616ps typ, 993ps min, 510ps max; typ from 1.06 V to 0 V
[Pulldown]
|Voltage   I(typ)   I(min)   I(max)
-2.4V     -30.64mA   -14.84mA   -44.29mA
-880mV    -30.64mA   -14.84mA   -44.29mA
-800mV    -30.64mA   -14.84mA   -42.37mA
-560mV    -23.52mA   -12.34mA   -33.09mA
0V        -765.1nA   -61.09nA   -2.527uA
400mV     13.38mA    4.998mA    20.91mA
720mV     20.62mA    6.178mA    33.69mA
880mV     22.92mA    6.306mA    38.42mA
1.04V     24.19mA    6.384mA    41.49mA
1.6V      25.46mA    6.543mA    44.41mA
4.08V     27.12mA    7.07mA     47.39mA
4.8V      28.77mA    7.815mA    50.01mA
[Pullup]
|Voltage   I(typ)   I(min)   I(max)
-2.4V     27.74mA    11.99mA    44.75mA
-800mV    27.74mA    11.99mA    44.06mA
-560mV    22.49mA    10.76mA    34.07mA
-160mV    6.354mA    3mA        8.973mA
240mV     -7.653mA   -3.251mA   -12mA
560mV     -15.22mA   -5.43mA    -24.63mA
800mV     -18.73mA   -5.909mA   -31mA
1.28V     -21.13mA   -6.237mA   -35.54mA
2.48V     -22.51mA   -6.819mA   -37.93mA
3.36V     -23.83mA   -15.37mA   -38.77mA
3.76V     -31.49mA   -15.37mA   -41.07mA
4.72V     -56mA      -15.37mA   -68.86mA
[GND_clamp]
|Voltage   I(typ)   I(min)   I(max)
-2.4V     -1.379A    -1.445A    -1.35A
-1.2V     -225.9mA   -297.5mA   -189.2mA
-1.15V    -182mA     -253.1mA   -145.3mA
-1.1V     -139.6mA   -209.7mA   -103.5mA
-1.05V    -99.62mA   -167.6mA   -65.7mA
-1V       -63.68mA   -127.3mA   -35.9mA
-950mV    -35mA      -89.93mA   -19.88mA
-900mV    -17.68mA   -57.02mA   -14.13mA
-850mV    -10.5mA    -31.19mA   -11.01mA
-750mV    -5.3mA     -7.337mA   -6.005mA
-450mV    -43.41uA   -101.2uA   -21.28uA
2.35V     52.68uA    50.02uA    36.83uA
[POWER_clamp]
|Voltage   I(typ)   I(min)   I(max)
-2.4V     0A         0A         65.17nA
-300mV    0A         0A         65.17nA
-270mV    0A         0A         0A
0V        0A         0A         0A
[Ramp]
| variable   typ   min   max
dV/dt_r  0.63713/9.29379n   0.18752/24.69273n   1.01518/4.78993n
dV/dt_f  0.74040/10.10463n   0.19470/27.10829n   1.11768/5.04252n
R_load = 50.000000
[Rising Waveform]
R_fixture= 50.000000
V_fixture= 2.400000
V_fixture_min= 1.650000
V_fixture_max= 2.700000
|time   V(typ)   V(min)   V(max)
0s        1.165V     1.324V     836.7mV
840.8ps   1.164V     1.324V     895.2mV
961ps     1.163V     1.324V     1.147V
1.281ns   1.159V     1.324V     2.336V
1.882ns   1.285V     1.324V     2.673V
2.362ns   2.181V     1.324V     2.692V
3.003ns   2.38V      1.324V     2.694V
5.606ns   2.396V     1.346V     2.696V
7.447ns   2.396V     1.642V     2.697V
19.94ns   2.399V     1.649V     2.699V
[Rising Waveform]
R_fixture= 50.000000
V_fixture= 0.0
V_fixture_min= 0.0
V_fixture_max= 0.0
|time   V(typ)   V(min)   V(max)
0s        146.2uV    47.39uV    204.7uV
4.505ns   -956.6uV   138.8uV    85.7mV
8.509ns   38.5mV     -594.2uV   1.045V
11.51ns   258.3mV    -197.6uV   1.462V
14.51ns   513.3mV    -200.2uV   1.617V
18.52ns   772.4mV    -174.1uV   1.675V
25.53ns   981.8mV    940.2uV    1.691V
37.04ns   1.053V     71.84mV    1.692V
80.58ns   1.062V     299.3mV    1.692V
249.2ns   1.062V     312.5mV    1.692V
[Falling Waveform]
R_fixture= 50.000000
V_fixture= 2.400000
V_fixture_min= 1.650000
V_fixture_max= 2.700000
|time   V(typ)   V(min)   V(max)
0s        2.399V     1.649V     2.699V
6.507ns   2.399V     1.655V     2.655V
8.008ns   2.397V     1.649V     2.441V
12.01ns   2.367V     1.648V     1.526V
14.51ns   2.263V     1.648V     1.082V
20.52ns   1.798V     1.648V     875.9mV
28.53ns   1.34V      1.648V     844.7mV
44.54ns   1.188V     1.612V     837.1mV
95.6ns    1.165V     1.346V     836.7mV
249.2ns   1.165V     1.324V     836.7mV
[Falling Waveform]
R_fixture= 50.000000
V_fixture= 0.0
V_fixture_min= 0.0
V_fixture_max= 0.0
|time   V(typ)   V(min)   V(max)
0s        1.062V     312.5mV    1.692V
1.361ns   1.062V     312.5mV    1.702V
2.082ns   1.064V     312.5mV    334.6mV
2.603ns   1.074V     312.5mV    61.67mV
2.883ns   835.5mV    312.5mV    25.33mV
3.443ns   236.4mV    312.2mV    5.134mV
4.324ns   18.52mV    315mV      1.976mV
5.606ns   963.2uV    319.3mV    1.752mV
8.208ns   563.9uV    8.174mV    1.124mV
19.94ns   146.2uV    47.39uV    204.7uV
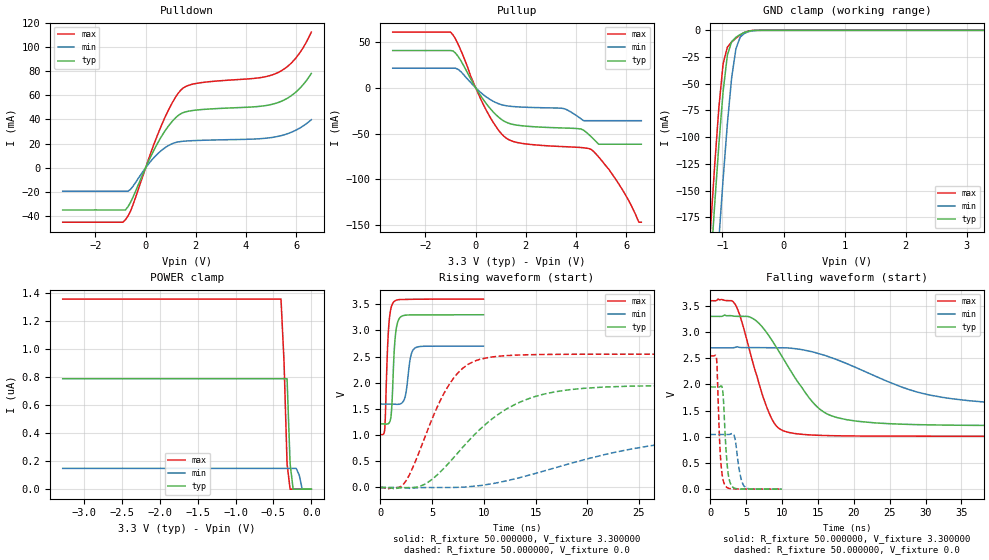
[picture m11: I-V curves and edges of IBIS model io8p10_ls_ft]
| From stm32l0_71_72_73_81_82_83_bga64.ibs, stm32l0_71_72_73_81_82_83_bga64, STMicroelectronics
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|   Model io8p10_ls_ft
[Model]  io8p10_ls_ft
Model_type I/O
Polarity   Non-Inverting
Enable   Active-Low
Vinl =   0.990000V
Vinh =   2.310000V
Vmeas =  1.650000V
Cref =   50.000000pF
Rref =   100.000000M
Vref =   0.0V
C_comp   4.606100pF   4.563500pF   4.706200pF
[Temperature Range]   25.000000   0.125000k   -40.000000
[Pullup Reference]   3.300000V   2.700000V   3.600000V
[Pulldown Reference]   0.0V   0.0V   0.0V
[POWER Clamp Reference]   3.300000V   2.700000V   3.600000V
[GND Clamp Reference]   0.0V   0.0V   0.0V
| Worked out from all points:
|   slope of the pulldown table from 0 to 0.495 V, typ, clamps not added: 23.6 ohm
|   slope of the pullup table from 0 to 0.495 V, typ, clamps not added: 24.9 ohm
|   GND clamp passes 1 mA (typ) near -0.59 V on its own axis
|   rising waveform, R_fixture 50.000000, V_fixture 3.300000: 20-80 % time 317ps typ, 426ps min, 300ps max; typ from 1.21 V to 3.3 V
|   rising waveform, R_fixture 50.000000, V_fixture 0.0: 20-80 % time 6.52ns typ, 13.6ns min, 3.48ns max; typ from 0 V to 1.95 V
|   falling waveform, R_fixture 50.000000, V_fixture 3.300000: 20-80 % time 6.07ns typ, 12.5ns min, 3.34ns max; typ from 3.3 V to 1.21 V
|   falling waveform, R_fixture 50.000000, V_fixture 0.0: 20-80 % time 521ps typ, 684ps min, 459ps max; typ from 1.95 V to 0 V
[Pulldown]
|Voltage   I(typ)   I(min)   I(max)
-3.3V     -34.78mA   -19.34mA   -44.89mA
-900mV    -34.78mA   -19.34mA   -44.89mA
-800mV    -34.78mA   -19.34mA   -42.84mA
-600mV    -28.56mA   -17.8mA    -35.75mA
100mV     4.638mA    2.744mA    6.076mA
600mV     24.8mA     13.84mA    33.52mA
1V        36.93mA    19.39mA    51.35mA
1.4V      44.67mA    21.76mA    64.17mA
2V        47.71mA    22.58mA    69.7mA
5.2V      53.44mA    25.71mA    78.05mA
6V        62.9mA     31.28mA    91.14mA
6.6V      77.96mA    39.76mA    112.2mA
[Pullup]
|Voltage   I(typ)   I(min)   I(max)
-3.3V     40.49mA    21.18mA    60.57mA
-1V       40.49mA    21.18mA    60.57mA
-700mV    34.22mA    19.98mA    47.65mA
400mV     -16.48mA   -9.566mA   -23.24mA
1.1V      -35.89mA   -19.06mA   -52.22mA
1.7V      -41.02mA   -20.95mA   -60.01mA
3.5V      -43.95mA   -22.7mA    -64.24mA
4.2V      -45.08mA   -33.97mA   -65.24mA
4.6V      -53.38mA   -35.99mA   -67.23mA
4.9V      -61.64mA   -35.99mA   -75.5mA
6.5V      -61.64mA   -35.99mA   -146.6mA
6.6V      -61.64mA   -35.99mA   -146.6mA
[GND_clamp]
|Voltage   I(typ)   I(min)   I(max)
-3.3V     -2.276A    -2.356A    -2.25A
-1.2V     -226mA     -318.7mA   -189.2mA
-1.13V    -164.9mA   -256.6mA   -128.3mA
-1.06V    -107.5mA   -196.5mA   -72.78mA
-990mV    -57.32mA   -139.4mA   -31.39mA
-920mV    -23.22mA   -87.32mA   -15.73mA
-850mV    -10.58mA   -44.45mA   -10.94mA
-780mV    -6.539mA   -17.25mA   -7.356mA
-710mV    -3.933mA   -6.349mA   -4.308mA
-640mV    -1.955mA   -2.79mA    -1.975mA
-360mV    -2.06uA    -16.21uA   -459.5nA
3.28V     0A         0A         0A
[POWER_clamp]
|Voltage   I(typ)   I(min)   I(max)
-3.28V    786.7nA    148nA      1.355uA
-400mV    786.7nA    148nA      1.355uA
-360mV    786.7nA    148nA      908.2nA
-320mV    786.7nA    148nA      180.5nA
-280mV    182.6nA    148nA      0A
-240mV    0A         148nA      0A
-200mV    0A         148nA      0A
-160mV    0A         101.6nA    0A
-120mV    0A         0A         0A
0V        0A         0A         0A
[Ramp]
| variable   typ   min   max
dV/dt_r  1.17105/6.49928n   0.61883/13.51716n   1.52766/3.47752n
dV/dt_f  1.25130/6.06589n   0.64062/12.41457n   1.55292/3.33245n
R_load = 50.000000
[Rising Waveform]
R_fixture= 50.000000
V_fixture= 3.300000
V_fixture_min= 2.700000
V_fixture_max= 3.600000
|time   V(typ)   V(min)   V(max)
0s        1.214V     1.593V     1.012V
440.4ps   1.212V     1.593V     1.141V
740.7ps   1.216V     1.593V     2.83V
1.001ns   1.312V     1.593V     3.392V
1.121ns   1.58V      1.593V     3.482V
1.281ns   2.338V     1.591V     3.541V
1.542ns   3.03V      1.589V     3.577V
2.062ns   3.271V     1.609V     3.591V
3.303ns   3.297V     2.656V     3.595V
9.97ns    3.3V       2.7V       3.599V
[Rising Waveform]
R_fixture= 50.000000
V_fixture= 0.0
V_fixture_min= 0.0
V_fixture_max= 0.0
|time   V(typ)   V(min)   V(max)
0s        172.6uV    66.63uV    964.9uV
2.402ns   -2.749mV   -5.253mV   102.4mV
4.304ns   63.99mV    -1.095mV   956.8mV
6.507ns   441.8mV    -339.5uV   1.919V
8.008ns   776.7mV    6.189mV    2.284V
9.61ns    1.106V     35.47mV    2.447V
13.71ns   1.649V     200.3mV    2.532V
18.32ns   1.868V     456.3mV    2.544V
31.43ns   1.949V     922.1mV    2.546V
49.85ns   1.952V     1.044V     2.546V
[Falling Waveform]
R_fixture= 50.000000
V_fixture= 3.300000
V_fixture_min= 2.700000
V_fixture_max= 3.600000
|time   V(typ)   V(min)   V(max)
0s        3.3V       2.7V       3.599V
3.504ns   3.302V     2.709V     3.522V
5.706ns   3.275V     2.703V     2.533V
7.808ns   3V         2.702V     1.589V
9.009ns   2.754V     2.701V     1.241V
10.21ns   2.486V     2.7V       1.113V
14.41ns   1.64V      2.617V     1.033V
17.72ns   1.365V     2.469V     1.02V
30.63ns   1.228V     1.797V     1.012V
49.85ns   1.214V     1.593V     1.012V
[Falling Waveform]
R_fixture= 50.000000
V_fixture= 0.0
V_fixture_min= 0.0
V_fixture_max= 0.0
|time   V(typ)   V(min)   V(max)
0s        1.952V     1.044V     2.546V
860.9ps   1.952V     1.044V     2.507V
1.421ns   1.963V     1.044V     615.5mV
1.742ns   1.869V     1.044V     205.8mV
2.042ns   1.119V     1.044V     76.06mV
2.482ns   309.4mV    1.044V     21.43mV
3.103ns   43.19mV    1.064V     7.06mV
4.204ns   3.234mV    250.4mV    4.392mV
4.765ns   2.042mV    51.65mV    3.074mV
9.97ns    172.6uV    66.63uV    964.9uV
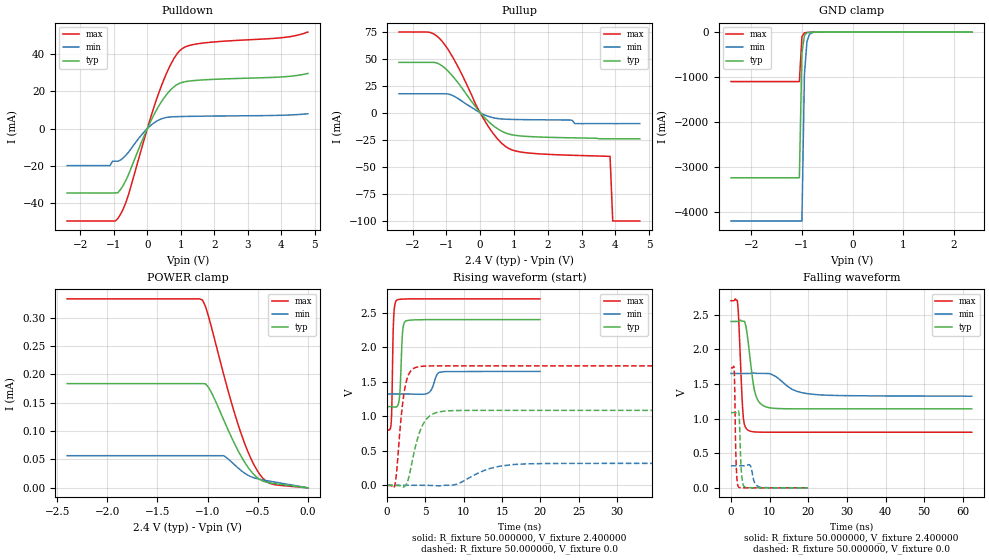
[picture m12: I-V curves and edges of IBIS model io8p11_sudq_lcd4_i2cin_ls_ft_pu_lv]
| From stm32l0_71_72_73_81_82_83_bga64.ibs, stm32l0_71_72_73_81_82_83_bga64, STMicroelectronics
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|   Model io8p11_sudq_lcd4_i2cin_ls_ft_pu_lv
[Model]  io8p11_sudq_lcd4_i2cin_ls_ft_pu_lv
Model_type I/O
Polarity   Non-Inverting
Enable   Active-Low
Vinl =   0.720000V
Vinh =   1.680000V
Vmeas =  1.200000V
Cref =   50.000000pF
Rref =   100.000000M
Vref =   0.0V
C_comp   2.470900pF   2.435200pF   2.490500pF
[Temperature Range]   25.000000   0.105000k   -40.000000
[Pullup Reference]   2.400000V   1.650000V   2.700000V
[Pulldown Reference]   0.0V   0.0V   0.0V
[POWER Clamp Reference]   2.400000V   1.650000V   2.700000V
[GND Clamp Reference]   0.0V   0.0V   0.0V
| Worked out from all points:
|   slope of the pulldown table from 0 to 0.36 V, typ, clamps not added: 28.5 ohm
|   slope of the pullup table from 0 to 0.36 V, typ, clamps not added: 32.2 ohm
|   GND clamp passes 1 mA (typ) near -0.64 V on its own axis
|   rising waveform, R_fixture 50.000000, V_fixture 2.400000: 20-80 % time 284ps typ, 635ps min, 195ps max; typ from 1.14 V to 2.4 V
|   rising waveform, R_fixture 50.000000, V_fixture 0.0: 20-80 % time 1.58ns typ, 3.82ns min, 923ps max; typ from 0.001 V to 1.09 V
|   falling waveform, R_fixture 50.000000, V_fixture 2.400000: 20-80 % time 1.79ns typ, 5.22ns min, 901ps max; typ from 2.4 V to 1.14 V
|   falling waveform, R_fixture 50.000000, V_fixture 0.0: 20-80 % time 466ps typ, 846ps min, 367ps max; typ from 1.09 V to 0.001 V
[Pulldown]
|Voltage   I(typ)   I(min)   I(max)
-2.4V     -34.71mA   -20mA      -49.82mA
-1.12V    -34.71mA   -20mA      -49.82mA
-1.04V    -34.71mA   -17.6mA    -49.82mA
-880mV    -34.55mA   -17.6mA    -48.46mA
-560mV    -24.65mA   -12.68mA   -35.33mA
0V        0A         0A         0A
400mV     13.84mA    5.066mA    22.03mA
720mV     21.25mA    6.254mA    35.26mA
1.04V     24.83mA    6.464mA    43.02mA
1.6V      26.11mA    6.627mA    45.88mA
4V        27.76mA    7.125mA    48.87mA
4.8V      29.64mA    7.94mA     51.96mA
[Pullup]
|Voltage   I(typ)   I(min)   I(max)
-2.4V     46.57mA    17.6mA     74.62mA
-1.52V    46.57mA    17.6mA     74.51mA
-1.2V     44.84mA    17.6mA     68.64mA
-720mV    30.34mA    14.43mA    46.24mA
-160mV    6.617mA    3.074mA    9.467mA
160mV     -5.477mA   -2.361mA   -8.695mA
480mV     -14.04mA   -5.167mA   -22.91mA
800mV     -19.21mA   -5.978mA   -32.18mA
1.52V     -22.07mA   -6.4mA     -37.42mA
3.84V     -24mA      -10mA      -40.2mA
3.92V     -24mA      -10mA      -100mA
4.72V     -24mA      -10mA      -100mA
[GND_clamp]
|Voltage   I(typ)   I(min)   I(max)
-2.4V     -3.237A    -4.197A    -1.1A
-1.05V    -3.237A    -4.197A    -1.1A
-1V       -475.5mA   -4.197A    -104.1mA
-950mV    -76.08mA   -935.1mA   -18.44mA
-900mV    -16.57mA   -212.6mA   -9.263mA
-850mV    -6.62mA    -50.88mA   -6.764mA
-800mV    -4.092mA   -13.84mA   -4.994mA
-650mV    -1.07mA    -1.21mA    -1.175mA
2.35V     0A         0A         0A
[POWER_clamp]
|Voltage   I(typ)   I(min)   I(max)
-2.4V     183.7uA    56.67uA    333uA
-1.05V    183.7uA    56.67uA    330.8uA
-1.02V    183.2uA    56.67uA    319.3uA
-960mV    167.4uA    56.67uA    282.2uA
-840mV    120.1uA    56.67uA    200.3uA
-750mV    84.75uA    43.78uA    142.9uA
-690mV    63.55uA    34.11uA    108.5uA
-600mV    37.04uA    22.45uA    64.63uA
-510mV    18.73uA    16.35uA    31.91uA
-450mV    12.06uA    14.02uA    17.25uA
-360mV    8.154uA    11.11uA    6.782uA
0V        0A         0A         0A
[Ramp]
| variable   typ   min   max
dV/dt_r  0.65095/1.57689n   0.19037/3.81345n   1.03799/0.92070n
dV/dt_f  0.75618/1.79071n   0.19410/5.20586n   1.13779/0.89869n
R_load = 50.000000
[Rising Waveform]
R_fixture= 50.000000
V_fixture= 2.400000
V_fixture_min= 1.650000
V_fixture_max= 2.700000
|time   V(typ)   V(min)   V(max)
0s        1.14V      1.323V     802.6mV
560.6ps   1.139V     1.323V     922.5mV
840.8ps   1.136V     1.323V     2.349V
1.241ns   1.137V     1.323V     2.679V
1.642ns   1.29V      1.323V     2.693V
2.082ns   2.272V     1.323V     2.697V
2.442ns   2.379V     1.323V     2.698V
5.365ns   2.399V     1.337V     2.7V
7.127ns   2.4V       1.642V     2.7V
19.94ns   2.4V       1.65V      2.7V
[Rising Waveform]
R_fixture= 50.000000
V_fixture= 0.0
V_fixture_min= 0.0
V_fixture_max= 0.0
|time   V(typ)   V(min)   V(max)
0s        878uV      1.336mV    740.1uV
1.001ns   988.9uV    1.333mV    -9.992mV
1.251ns   171.7uV    1.33mV     183.2mV
1.877ns   -9.692mV   1.327mV    1.023V
2.377ns   -4.441mV   1.343mV    1.433V
4.004ns   684.7mV    1.414mV    1.715V
5.38ns    987.2mV    -155.6uV   1.728V
7.883ns   1.079V     1.455mV    1.73V
16.52ns   1.086V     302mV      1.73V
62.31ns   1.086V     318.6mV    1.73V
[Falling Waveform]
R_fixture= 50.000000
V_fixture= 2.400000
V_fixture_min= 1.650000
V_fixture_max= 2.700000
|time   V(typ)   V(min)   V(max)
0s        2.4V       1.65V      2.7V
1.752ns   2.4V       1.65V      2.654V
2.002ns   2.401V     1.65V      2.432V
3.128ns   2.403V     1.65V      1.068V
3.754ns   2.356V     1.65V      875.3mV
4.505ns   2.081V     1.65V      829.9mV
6.256ns   1.367V     1.653V     806.8mV
9.259ns   1.165V     1.65V      803mV
19.77ns   1.14V      1.359V     802.6mV
62.31ns   1.14V      1.323V     802.6mV
[Falling Waveform]
R_fixture= 50.000000
V_fixture= 0.0
V_fixture_min= 0.0
V_fixture_max= 0.0
|time   V(typ)   V(min)   V(max)
0s        1.086V     318.6mV    1.73V
840.8ps   1.086V     318.6mV    1.707V
1.361ns   1.085V     318.6mV    336.4mV
1.962ns   1.109V     318.6mV    12.96mV
2.202ns   958.9mV    318.6mV    4.928mV
2.683ns   249.7mV    318.4mV    2.655mV
3.403ns   20.96mV    318.5mV    1.789mV
4.925ns   2.674mV    328.2mV    1.01mV
7.608ns   1.264mV    8.525mV    763.3uV
19.94ns   878uV      1.336mV    740.1uV
